# LEF file generated by Abstract Generator version 5.5.10 on Jul 31 16:51:52 2004
#
# Contains LEF for all bins.
# Options:   [x] Antenna
#            [x] Geometry
#            [x] Technology

VERSION 5.4 ;
NAMESCASESENSITIVE ON ;
BUSBITCHARS "[]" ;
DIVIDERCHAR "/" ;
UNITS
  DATABASE MICRONS 1000 ;
END UNITS

USEMINSPACING OBS ON ;
USEMINSPACING PIN OFF ;
CLEARANCEMEASURE EUCLIDEAN ;


MANUFACTURINGGRID 0.15 ;

LAYER nwell
  TYPE	MASTERSLICE ;
END nwell

LAYER nactive
  TYPE	MASTERSLICE ;
END nactive

LAYER pactive
  TYPE	MASTERSLICE ;
END pactive

LAYER poly
  TYPE	MASTERSLICE ;
END poly

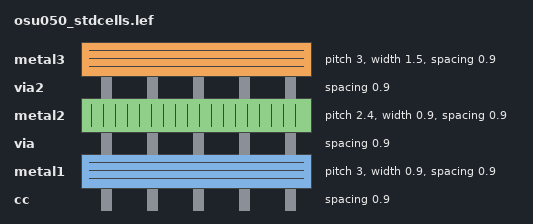
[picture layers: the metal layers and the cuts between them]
LAYER cc
  TYPE	CUT ;
  SPACING	0.9 ;
END cc

LAYER metal1
  TYPE		ROUTING ;
  DIRECTION	HORIZONTAL ;
  PITCH		3  ;
  OFFSET	1.5 ;
  WIDTH		0.9 ;
  SPACING	0.9 ;
  RESISTANCE	RPERSQ 0.09 ;
  CAPACITANCE	CPERSQDIST 3.2e-05 ;
END metal1

LAYER via
  TYPE	CUT ;
  SPACING	0.9 ;
END via

LAYER metal2
  TYPE		ROUTING ;
  DIRECTION	VERTICAL ;
  PITCH		2.4  ;
  OFFSET	1.2 ;
  WIDTH		0.9 ;
  SPACING	0.9 ;
  RESISTANCE	RPERSQ 0.09 ;
  CAPACITANCE	CPERSQDIST 1.6e-05 ;
END metal2

LAYER via2
  TYPE	CUT ;
  SPACING	0.9 ;
END via2

LAYER metal3
  TYPE		ROUTING ;
  DIRECTION	HORIZONTAL ;
  PITCH		3  ;
  OFFSET	1.5 ;
  WIDTH		1.5 ;
  SPACING	0.9 ;
  RESISTANCE	RPERSQ 0.05 ;
  CAPACITANCE	CPERSQDIST 1e-05 ;
END metal3

SPACING
  SAMENET cc  via	0.150 ;
  SAMENET via  via2	0.150 ;
END SPACING

VIA M2_M1 DEFAULT
  LAYER metal1 ;
    RECT -0.600 -0.600 0.600 0.600 ;
  LAYER via ;
    RECT -0.300 -0.300 0.300 0.300 ;
  LAYER metal2 ;
    RECT -0.600 -0.600 0.600 0.600 ;
END M2_M1

VIA M3_M2 DEFAULT
  LAYER metal2 ;
    RECT -0.600 -0.600 0.600 0.600 ;
  LAYER via2 ;
    RECT -0.300 -0.300 0.300 0.300 ;
  LAYER metal3 ;
    RECT -0.900 -0.900 0.900 0.900 ;
END M3_M2


VIARULE viagen21 GENERATE
  LAYER metal1 ;
    DIRECTION HORIZONTAL ;
    WIDTH 1.2 TO 120 ;
    OVERHANG 0.3 ;
    METALOVERHANG 0 ;
  LAYER metal2 ;
    DIRECTION VERTICAL ;
    WIDTH 1.2 TO 120 ;
    OVERHANG 0.3 ;
    METALOVERHANG 0 ;
  LAYER via ;
    RECT -0.3 -0.3 0.3 0.3 ;
    SPACING 1.5 BY 1.5 ;
END viagen21

VIARULE viagen32 GENERATE
  LAYER metal3 ;
    DIRECTION HORIZONTAL ;
    WIDTH 1.8 TO 180 ;
    OVERHANG 0.6 ;
    METALOVERHANG 0 ;
  LAYER metal2 ;
    DIRECTION VERTICAL ;
    WIDTH 1.2 TO 120 ;
    OVERHANG 0.6 ;
    METALOVERHANG 0 ;
  LAYER via2 ;
    RECT -0.3 -0.3 0.3 0.3 ;
    SPACING 2.1 BY 2.1 ;
END viagen32

VIARULE TURN1 GENERATE
  LAYER metal1 ;
    DIRECTION HORIZONTAL ;
  LAYER metal1 ;
    DIRECTION VERTICAL ;
END TURN1

VIARULE TURN2 GENERATE
  LAYER metal2 ;
    DIRECTION HORIZONTAL ;
  LAYER metal2 ;
    DIRECTION VERTICAL ;
END TURN2

VIARULE TURN3 GENERATE
  LAYER metal3 ;
    DIRECTION HORIZONTAL ;
  LAYER metal3 ;
    DIRECTION VERTICAL ;
END TURN3

SITE  corner
    CLASS	PAD ;
    SYMMETRY	R90 Y ;
    SIZE	300.000 BY 300.000 ;
END  corner

SITE  IO
    CLASS	PAD ;
    SYMMETRY	Y ;
    SIZE	90.000 BY 300.000 ;
END  IO

SITE  core
    CLASS	CORE ;
    SYMMETRY	Y ;
    SIZE	2.400 BY 30.000 ;
END  core

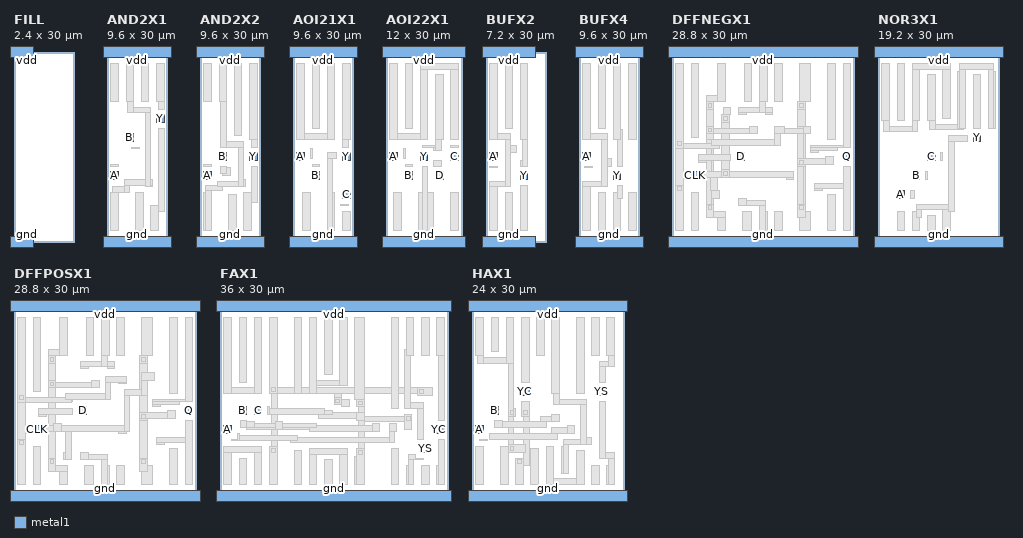
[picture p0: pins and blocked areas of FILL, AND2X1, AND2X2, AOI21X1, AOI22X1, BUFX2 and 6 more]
MACRO FILL
  CLASS  CORE ;
  FOREIGN FILL 0.000 0.000 ;
  ORIGIN 0.000 0.000 ;
  SIZE 2.400 BY 30.000 ;
  SYMMETRY X Y  ;
  SITE core ;
  PIN gnd
    DIRECTION INOUT ;
    USE GROUND ;
    SHAPE ABUTMENT ;
    PORT
      LAYER metal1 ;
        RECT -0.600 -0.900 3.000 0.900 ;
    END
  END gnd
  PIN vdd
    DIRECTION INOUT ;
    USE POWER ;
    SHAPE ABUTMENT ;
    PORT
      LAYER metal1 ;
        RECT -0.600 29.100 3.000 30.900 ;
    END
  END vdd
END FILL

MACRO AND2X1
  CLASS  CORE ;
  FOREIGN AND2X1 0.000 0.000 ;
  ORIGIN 0.000 0.000 ;
  SIZE 9.600 BY 30.000 ;
  SYMMETRY X Y  ;
  SITE core ;
  PIN A
    DIRECTION INPUT ;
    PORT
      LAYER metal1 ;
        RECT 0.600 9.900 1.800 11.100 ;
    END
  END A
  PIN B
    DIRECTION INPUT ;
    PORT
      LAYER metal1 ;
        RECT 3.000 15.900 4.200 17.100 ;
    END
  END B
  PIN gnd
    DIRECTION INOUT ;
    USE GROUND ;
    SHAPE ABUTMENT ;
    PORT
      LAYER metal1 ;
        RECT -0.600 -0.900 10.200 0.900 ;
    END
  END gnd
  PIN Y
    DIRECTION OUTPUT ;
    PORT
      LAYER metal1 ;
        RECT 7.800 18.900 9.000 20.100 ;
    END
  END Y
  PIN vdd
    DIRECTION INOUT ;
    USE POWER ;
    SHAPE ABUTMENT ;
    PORT
      LAYER metal1 ;
        RECT -0.600 29.100 10.200 30.900 ;
    END
  END vdd
  OBS 
      LAYER metal1 ;
        RECT 0.600 22.200 1.800 28.200 ;
        RECT 0.600 12.000 1.800 12.300 ;
        RECT 3.900 14.700 5.100 15.000 ;
        RECT 4.500 1.800 5.700 7.800 ;
        RECT 5.400 22.200 6.600 28.200 ;
        RECT 0.600 1.800 1.800 7.800 ;
        RECT 0.900 7.800 3.600 8.700 ;
        RECT 2.700 7.800 3.600 9.900 ;
        RECT 6.000 8.700 7.200 9.900 ;
        RECT 2.700 9.000 7.200 9.900 ;
        RECT 6.000 8.700 6.900 21.300 ;
        RECT 3.300 20.400 6.900 21.300 ;
        RECT 3.300 20.400 4.200 28.200 ;
        RECT 3.000 22.200 4.200 28.200 ;
        RECT 8.100 21.000 9.000 28.200 ;
        RECT 7.800 22.200 9.000 28.200 ;
        RECT 6.900 1.800 8.100 5.700 ;
        RECT 8.100 4.800 9.000 18.000 ;
  END 
END AND2X1

MACRO AND2X2
  CLASS  CORE ;
  FOREIGN AND2X2 0.000 0.000 ;
  ORIGIN 0.000 0.000 ;
  SIZE 9.600 BY 30.000 ;
  SYMMETRY X Y  ;
  SITE core ;
  PIN A
    DIRECTION INPUT ;
    PORT
      LAYER metal1 ;
        RECT 0.600 9.900 1.800 11.100 ;
    END
  END A
  PIN B
    DIRECTION INPUT ;
    PORT
      LAYER metal1 ;
        RECT 3.000 12.900 4.200 14.100 ;
    END
  END B
  PIN gnd
    DIRECTION INOUT ;
    USE GROUND ;
    SHAPE ABUTMENT ;
    PORT
      LAYER metal1 ;
        RECT -0.600 -0.900 10.200 0.900 ;
    END
  END gnd
  PIN Y
    DIRECTION OUTPUT ;
    PORT
      LAYER metal1 ;
        RECT 7.800 12.900 9.000 14.100 ;
    END
  END Y
  PIN vdd
    DIRECTION INOUT ;
    USE POWER ;
    SHAPE ABUTMENT ;
    PORT
      LAYER metal1 ;
        RECT -0.600 29.100 10.200 30.900 ;
    END
  END vdd
  OBS 
      LAYER metal1 ;
        RECT 0.600 22.200 1.800 28.200 ;
        RECT 0.600 12.000 1.800 12.300 ;
        RECT 3.600 10.500 4.800 11.700 ;
        RECT 3.300 10.800 4.200 12.000 ;
        RECT 4.500 1.800 5.700 7.500 ;
        RECT 5.400 16.800 6.600 28.200 ;
        RECT 0.600 1.800 1.800 7.800 ;
        RECT 0.900 1.800 1.800 9.000 ;
        RECT 0.900 8.100 3.600 9.000 ;
        RECT 2.700 8.700 7.200 9.600 ;
        RECT 6.000 8.700 7.200 9.900 ;
        RECT 6.000 8.700 6.900 15.900 ;
        RECT 3.300 15.000 6.900 15.900 ;
        RECT 3.300 15.000 4.200 28.200 ;
        RECT 3.000 22.200 4.200 28.200 ;
        RECT 8.100 15.000 9.000 28.200 ;
        RECT 7.800 16.200 9.000 28.200 ;
        RECT 6.900 1.800 8.100 7.800 ;
        RECT 8.100 6.300 9.000 12.000 ;
  END 
END AND2X2

MACRO AOI21X1
  CLASS  CORE ;
  FOREIGN AOI21X1 0.000 0.000 ;
  ORIGIN 0.000 0.000 ;
  SIZE 9.600 BY 30.000 ;
  SYMMETRY X Y  ;
  SITE core ;
  PIN A
    DIRECTION INPUT ;
    PORT
      LAYER metal1 ;
        RECT 0.600 12.900 1.800 14.100 ;
    END
  END A
  PIN B
    DIRECTION INPUT ;
    PORT
      LAYER metal1 ;
        RECT 3.000 9.900 4.200 11.100 ;
    END
  END B
  PIN C
    DIRECTION INPUT ;
    PORT
      LAYER metal1 ;
        RECT 7.800 6.900 9.000 8.100 ;
    END
  END C
  PIN gnd
    DIRECTION INOUT ;
    USE GROUND ;
    SHAPE ABUTMENT ;
    PORT
      LAYER metal1 ;
        RECT -0.600 -0.900 10.200 0.900 ;
    END
  END gnd
  PIN Y
    DIRECTION OUTPUT ;
    PORT
      LAYER metal1 ;
        RECT 7.800 12.900 9.000 14.100 ;
    END
  END Y
  PIN vdd
    DIRECTION INOUT ;
    USE POWER ;
    SHAPE ABUTMENT ;
    PORT
      LAYER metal1 ;
        RECT -0.600 29.100 10.200 30.900 ;
    END
  END vdd
  OBS 
      LAYER metal1 ;
        RECT 1.500 1.800 2.700 7.800 ;
        RECT 2.700 13.200 3.000 14.700 ;
        RECT 3.000 18.000 4.200 28.200 ;
        RECT 3.000 12.000 4.200 12.300 ;
        RECT 0.600 16.200 6.600 17.100 ;
        RECT 0.600 16.200 1.800 28.200 ;
        RECT 5.400 16.200 6.600 28.200 ;
        RECT 5.400 1.800 6.600 7.800 ;
        RECT 5.400 1.800 6.300 14.100 ;
        RECT 5.400 13.200 6.900 14.100 ;
        RECT 7.500 5.700 8.700 6.000 ;
        RECT 7.800 15.000 8.700 28.200 ;
        RECT 7.800 16.200 9.000 28.200 ;
        RECT 7.800 1.800 9.000 4.800 ;
  END 
END AOI21X1

MACRO AOI22X1
  CLASS  CORE ;
  FOREIGN AOI22X1 0.000 0.000 ;
  ORIGIN 0.000 0.000 ;
  SIZE 12.000 BY 30.000 ;
  SYMMETRY X Y  ;
  SITE core ;
  PIN A
    DIRECTION INPUT ;
    PORT
      LAYER metal1 ;
        RECT 0.600 12.900 1.800 14.100 ;
    END
  END A
  PIN B
    DIRECTION INPUT ;
    PORT
      LAYER metal1 ;
        RECT 3.000 9.900 4.200 11.100 ;
    END
  END B
  PIN C
    DIRECTION INPUT ;
    PORT
      LAYER metal1 ;
        RECT 10.200 12.900 11.400 14.100 ;
    END
  END C
  PIN D
    DIRECTION INPUT ;
    PORT
      LAYER metal1 ;
        RECT 7.800 9.900 9.000 11.100 ;
    END
  END D
  PIN gnd
    DIRECTION INOUT ;
    USE GROUND ;
    SHAPE ABUTMENT ;
    PORT
      LAYER metal1 ;
        RECT -0.600 -0.900 12.600 0.900 ;
    END
  END gnd
  PIN Y
    DIRECTION OUTPUT ;
    PORT
      LAYER metal1 ;
        RECT 5.400 12.900 6.600 14.100 ;
    END
  END Y
  PIN vdd
    DIRECTION INOUT ;
    USE POWER ;
    SHAPE ABUTMENT ;
    PORT
      LAYER metal1 ;
        RECT -0.600 29.100 12.600 30.900 ;
    END
  END vdd
  OBS 
      LAYER metal1 ;
        RECT 1.200 1.800 2.400 7.800 ;
        RECT 2.700 13.200 3.000 14.700 ;
        RECT 3.000 18.000 4.200 28.200 ;
        RECT 3.000 12.000 4.200 12.300 ;
        RECT 5.100 1.800 7.500 7.800 ;
        RECT 5.700 1.800 6.600 12.000 ;
        RECT 7.500 12.000 8.700 12.900 ;
        RECT 7.500 14.400 8.700 15.300 ;
        RECT 5.700 15.000 8.700 15.300 ;
        RECT 7.800 14.400 8.700 26.400 ;
        RECT 7.800 16.200 9.000 26.400 ;
        RECT 0.600 16.200 6.600 17.100 ;
        RECT 5.400 16.200 6.600 28.200 ;
        RECT 0.600 16.200 1.800 28.200 ;
        RECT 10.200 16.200 11.400 28.200 ;
        RECT 5.400 27.300 11.400 28.200 ;
        RECT 10.200 15.000 11.400 15.300 ;
        RECT 10.200 1.800 11.400 7.800 ;
  END 
END AOI22X1

MACRO BUFX2
  CLASS  CORE ;
  FOREIGN BUFX2 0.000 0.000 ;
  ORIGIN 0.000 0.000 ;
  SIZE 7.200 BY 30.000 ;
  SYMMETRY X Y  ;
  SITE core ;
  PIN A
    DIRECTION INPUT ;
    PORT
      LAYER metal1 ;
        RECT 0.600 12.900 1.800 14.100 ;
    END
  END A
  PIN gnd
    DIRECTION INOUT ;
    USE GROUND ;
    SHAPE ABUTMENT ;
    PORT
      LAYER metal1 ;
        RECT -0.600 -0.900 7.800 0.900 ;
    END
  END gnd
  PIN Y
    DIRECTION OUTPUT ;
    PORT
      LAYER metal1 ;
        RECT 5.400 9.900 6.600 11.100 ;
    END
  END Y
  PIN vdd
    DIRECTION INOUT ;
    USE POWER ;
    SHAPE ABUTMENT ;
    PORT
      LAYER metal1 ;
        RECT -0.600 29.100 7.800 30.900 ;
    END
  END vdd
  OBS 
      LAYER metal1 ;
        RECT 0.600 11.700 1.800 12.000 ;
        RECT 3.000 18.000 4.200 28.200 ;
        RECT 3.000 1.800 4.200 7.800 ;
        RECT 0.600 1.800 1.800 9.600 ;
        RECT 0.600 8.700 3.900 9.600 ;
        RECT 3.000 14.100 4.800 15.300 ;
        RECT 3.000 8.700 3.900 17.100 ;
        RECT 0.600 16.200 3.900 17.100 ;
        RECT 0.600 16.200 1.800 28.200 ;
        RECT 5.400 12.000 6.600 12.900 ;
        RECT 5.700 12.000 6.600 28.200 ;
        RECT 5.400 16.200 6.600 28.200 ;
        RECT 5.400 1.800 6.600 9.000 ;
  END 
END BUFX2

MACRO BUFX4
  CLASS  CORE ;
  FOREIGN BUFX4 0.000 0.000 ;
  ORIGIN 0.000 0.000 ;
  SIZE 9.600 BY 30.000 ;
  SYMMETRY X Y  ;
  SITE core ;
  PIN A
    DIRECTION INPUT ;
    PORT
      LAYER metal1 ;
        RECT 0.600 12.900 1.800 14.100 ;
    END
  END A
  PIN gnd
    DIRECTION INOUT ;
    USE GROUND ;
    SHAPE ABUTMENT ;
    PORT
      LAYER metal1 ;
        RECT -0.600 -0.900 10.200 0.900 ;
    END
  END gnd
  PIN Y
    DIRECTION OUTPUT ;
    PORT
      LAYER metal1 ;
        RECT 5.400 9.900 6.600 11.100 ;
    END
  END Y
  PIN vdd
    DIRECTION INOUT ;
    USE POWER ;
    SHAPE ABUTMENT ;
    PORT
      LAYER metal1 ;
        RECT -0.600 29.100 10.200 30.900 ;
    END
  END vdd
  OBS 
      LAYER metal1 ;
        RECT 0.900 11.700 2.100 12.000 ;
        RECT 3.000 18.000 4.200 28.200 ;
        RECT 3.000 1.800 4.200 7.800 ;
        RECT 0.600 1.800 1.800 9.600 ;
        RECT 0.600 8.700 4.500 9.600 ;
        RECT 3.600 12.000 5.100 13.200 ;
        RECT 3.600 8.700 4.500 17.100 ;
        RECT 0.600 16.200 4.500 17.100 ;
        RECT 0.600 16.200 1.800 28.200 ;
        RECT 6.000 12.000 6.900 17.700 ;
        RECT 5.400 16.200 6.600 28.200 ;
        RECT 5.400 1.800 6.600 7.800 ;
        RECT 6.000 6.900 6.900 9.000 ;
        RECT 7.800 16.200 9.000 28.200 ;
        RECT 7.800 1.800 9.000 7.800 ;
  END 
END BUFX4

MACRO DFFNEGX1
  CLASS  CORE ;
  FOREIGN DFFNEGX1 0.000 0.000 ;
  ORIGIN 0.000 0.000 ;
  SIZE 28.800 BY 30.000 ;
  SYMMETRY X Y  ;
  SITE core ;
  PIN Q
    DIRECTION OUTPUT ;
    PORT
      LAYER metal1 ;
        RECT 27.000 12.900 28.200 14.100 ;
    END
  END Q
  PIN CLK
    DIRECTION INPUT ;
    PORT
      LAYER metal1 ;
        RECT 3.000 9.900 4.200 11.100 ;
    END
  END CLK
  PIN D
    DIRECTION INPUT ;
    PORT
      LAYER metal1 ;
        RECT 10.200 12.900 11.400 14.100 ;
    END
  END D
  PIN gnd
    DIRECTION INOUT ;
    USE GROUND ;
    SHAPE ABUTMENT ;
    PORT
      LAYER metal1 ;
        RECT -0.600 -0.900 29.400 0.900 ;
    END
  END gnd
  PIN vdd
    DIRECTION INOUT ;
    USE POWER ;
    SHAPE ABUTMENT ;
    PORT
      LAYER metal1 ;
        RECT -0.600 29.100 29.400 30.900 ;
    END
  END vdd
  OBS 
      LAYER metal2 ;
        RECT 0.600 7.800 1.800 16.200 ;
        RECT 5.400 4.800 6.600 15.000 ;
        RECT 5.400 4.800 6.300 22.200 ;
        RECT 5.400 16.200 6.600 22.200 ;
        RECT 7.800 10.200 9.000 20.100 ;
        RECT 19.800 4.800 21.000 17.100 ;
        RECT 19.800 4.800 20.700 22.200 ;
        RECT 19.800 18.300 21.000 22.200 ;
      LAYER metal1 ;
        RECT 0.600 1.800 1.800 9.000 ;
        RECT 1.800 9.900 2.100 11.100 ;
        RECT 3.000 16.500 4.200 28.200 ;
        RECT 3.000 1.800 4.200 7.800 ;
        RECT 5.400 21.000 6.600 23.100 ;
        RECT 5.400 22.200 8.400 23.100 ;
        RECT 7.200 22.200 8.400 28.200 ;
        RECT 7.200 1.800 8.400 4.800 ;
        RECT 5.400 3.900 8.400 4.800 ;
        RECT 5.400 3.900 6.600 6.000 ;
        RECT 7.800 18.900 9.000 20.100 ;
        RECT 8.100 20.100 9.300 21.300 ;
        RECT 4.200 12.600 5.400 13.800 ;
        RECT 4.200 12.900 9.300 13.800 ;
        RECT 11.400 22.200 12.600 28.200 ;
        RECT 11.100 1.800 12.600 4.800 ;
        RECT 5.400 17.100 13.500 18.000 ;
        RECT 5.400 17.100 6.600 18.300 ;
        RECT 12.300 17.100 13.500 18.300 ;
        RECT 13.800 1.800 15.000 4.800 ;
        RECT 13.800 1.800 14.700 6.600 ;
        RECT 10.500 5.700 14.700 6.600 ;
        RECT 10.500 5.700 11.700 6.900 ;
        RECT 10.500 20.100 11.700 21.300 ;
        RECT 14.700 20.100 15.900 21.300 ;
        RECT 10.500 20.400 15.900 21.300 ;
        RECT 13.800 20.400 14.700 28.200 ;
        RECT 13.800 22.200 15.000 28.200 ;
        RECT 16.200 22.200 17.400 28.200 ;
        RECT 16.200 1.800 17.400 4.800 ;
        RECT 6.300 6.900 7.500 8.100 ;
        RECT 6.000 8.100 7.200 11.100 ;
        RECT 18.000 9.900 19.200 11.100 ;
        RECT 5.100 10.200 19.200 11.100 ;
        RECT 7.800 10.200 9.000 11.400 ;
        RECT 19.800 21.000 21.000 22.200 ;
        RECT 20.100 22.200 21.900 28.200 ;
        RECT 0.600 14.700 7.500 15.600 ;
        RECT 6.300 15.300 17.100 16.200 ;
        RECT 16.200 15.300 17.100 18.300 ;
        RECT 16.200 17.100 21.900 18.000 ;
        RECT 16.200 17.100 17.700 18.300 ;
        RECT 20.700 17.100 21.900 18.300 ;
        RECT 0.600 14.700 1.800 28.200 ;
        RECT 20.100 1.800 21.900 4.800 ;
        RECT 19.800 3.900 21.000 6.000 ;
        RECT 19.800 12.000 21.000 13.200 ;
        RECT 19.800 12.300 25.500 13.200 ;
        RECT 24.300 12.300 25.500 13.500 ;
        RECT 24.600 16.200 25.800 28.200 ;
        RECT 24.600 1.800 25.800 7.500 ;
        RECT 21.900 14.100 23.100 15.300 ;
        RECT 21.900 14.400 26.100 15.300 ;
        RECT 21.900 15.000 28.200 15.300 ;
        RECT 27.000 15.000 28.200 28.200 ;
        RECT 22.500 8.100 23.700 9.300 ;
        RECT 22.500 8.400 28.200 9.300 ;
        RECT 27.000 1.800 28.200 12.000 ;
      LAYER via ;
        RECT 0.900 15.300 1.500 15.900 ;
        RECT 0.900 8.100 1.500 8.700 ;
        RECT 5.700 21.300 6.300 21.900 ;
        RECT 5.700 17.400 6.300 18.000 ;
        RECT 5.700 5.100 6.300 5.700 ;
        RECT 8.100 19.200 8.700 19.800 ;
        RECT 8.100 10.500 8.700 11.100 ;
        RECT 20.100 21.300 20.700 21.900 ;
        RECT 20.100 12.300 20.700 12.900 ;
        RECT 20.100 5.100 20.700 5.700 ;
  END 
END DFFNEGX1

MACRO NOR3X1
  CLASS  CORE ;
  FOREIGN NOR3X1 0.000 0.000 ;
  ORIGIN 0.000 0.000 ;
  SIZE 19.200 BY 30.000 ;
  SYMMETRY X Y  ;
  SITE core ;
  PIN A
    DIRECTION INPUT ;
    PORT
      LAYER metal1 ;
        RECT 3.000 6.900 4.200 8.100 ;
    END
  END A
  PIN B
    DIRECTION INPUT ;
    PORT
      LAYER metal1 ;
        RECT 5.400 9.900 6.600 11.100 ;
    END
  END B
  PIN C
    DIRECTION INPUT ;
    PORT
      LAYER metal1 ;
        RECT 7.800 12.900 9.000 14.100 ;
    END
  END C
  PIN gnd
    DIRECTION INOUT ;
    USE GROUND ;
    SHAPE ABUTMENT ;
    PORT
      LAYER metal1 ;
        RECT -0.600 -0.900 19.800 0.900 ;
    END
  END gnd
  PIN Y
    DIRECTION OUTPUT ;
    PORT
      LAYER metal1 ;
        RECT 15.000 15.900 16.200 17.100 ;
    END
  END Y
  PIN vdd
    DIRECTION INOUT ;
    USE POWER ;
    SHAPE ABUTMENT ;
    PORT
      LAYER metal1 ;
        RECT -0.600 29.100 19.800 30.900 ;
    END
  END vdd
  OBS 
      LAYER metal1 ;
        RECT 3.000 19.200 4.200 28.200 ;
        RECT 3.000 1.800 4.200 4.800 ;
        RECT 5.100 6.900 5.700 8.100 ;
        RECT 7.500 9.900 7.800 11.100 ;
        RECT 7.800 1.800 9.000 4.200 ;
        RECT 9.900 12.900 10.200 14.100 ;
        RECT 0.900 17.400 6.300 18.300 ;
        RECT 5.400 17.400 6.300 28.200 ;
        RECT 5.400 19.200 6.600 28.200 ;
        RECT 0.900 17.400 1.800 28.200 ;
        RECT 0.600 19.200 1.800 28.200 ;
        RECT 10.200 19.500 11.400 28.200 ;
        RECT 5.400 27.300 11.400 28.200 ;
        RECT 5.400 1.800 6.600 4.800 ;
        RECT 6.000 3.900 6.900 6.000 ;
        RECT 10.200 1.800 11.400 6.000 ;
        RECT 6.000 5.100 12.000 6.000 ;
        RECT 11.100 4.800 12.000 16.800 ;
        RECT 11.100 15.900 14.100 16.800 ;
        RECT 15.000 18.000 16.200 26.400 ;
        RECT 8.100 17.700 13.500 18.600 ;
        RECT 8.100 17.700 9.000 26.400 ;
        RECT 7.800 19.200 9.000 26.400 ;
        RECT 12.600 18.000 13.800 27.000 ;
        RECT 17.400 18.000 18.600 27.000 ;
        RECT 12.900 18.000 13.800 28.200 ;
        RECT 17.400 18.000 18.300 28.200 ;
        RECT 12.900 27.300 18.300 28.200 ;
  END 
END NOR3X1

MACRO DFFPOSX1
  CLASS  CORE ;
  FOREIGN DFFPOSX1 0.000 0.000 ;
  ORIGIN 0.000 0.000 ;
  SIZE 28.800 BY 30.000 ;
  SYMMETRY X Y  ;
  SITE core ;
  PIN Q
    DIRECTION OUTPUT ;
    PORT
      LAYER metal1 ;
        RECT 27.000 12.900 28.200 14.100 ;
    END
  END Q
  PIN CLK
    DIRECTION INPUT ;
    PORT
      LAYER metal1 ;
        RECT 3.000 9.900 4.200 11.100 ;
    END
  END CLK
  PIN D
    DIRECTION INPUT ;
    PORT
      LAYER metal1 ;
        RECT 10.200 12.900 11.400 14.100 ;
    END
  END D
  PIN gnd
    DIRECTION INOUT ;
    USE GROUND ;
    SHAPE ABUTMENT ;
    PORT
      LAYER metal1 ;
        RECT -0.600 -0.900 29.400 0.900 ;
    END
  END gnd
  PIN vdd
    DIRECTION INOUT ;
    USE POWER ;
    SHAPE ABUTMENT ;
    PORT
      LAYER metal1 ;
        RECT -0.600 29.100 29.400 30.900 ;
    END
  END vdd
  OBS 
      LAYER metal2 ;
        RECT 0.600 7.800 1.800 16.200 ;
        RECT 5.400 4.800 6.600 22.200 ;
        RECT 19.800 4.800 21.000 22.200 ;
      LAYER metal1 ;
        RECT 0.600 1.800 1.800 9.000 ;
        RECT 1.800 9.900 2.100 11.100 ;
        RECT 3.000 16.500 4.200 28.200 ;
        RECT 3.000 1.800 4.200 7.800 ;
        RECT 5.400 21.000 6.600 23.100 ;
        RECT 5.400 22.200 8.400 23.100 ;
        RECT 7.200 22.200 8.400 28.200 ;
        RECT 7.200 1.800 8.400 4.800 ;
        RECT 5.400 3.900 8.400 4.800 ;
        RECT 5.400 3.900 6.600 6.000 ;
        RECT 3.900 12.600 5.100 13.800 ;
        RECT 3.900 12.900 9.300 13.800 ;
        RECT 11.400 22.200 12.600 28.200 ;
        RECT 11.100 1.800 12.600 4.800 ;
        RECT 5.400 17.100 13.500 18.000 ;
        RECT 5.400 17.100 6.600 18.300 ;
        RECT 12.300 17.100 13.500 18.300 ;
        RECT 13.800 1.800 15.000 4.800 ;
        RECT 13.800 1.800 14.700 6.600 ;
        RECT 10.500 5.700 14.700 6.600 ;
        RECT 10.500 5.700 11.700 6.900 ;
        RECT 10.500 20.100 11.700 21.300 ;
        RECT 14.700 20.100 15.900 21.300 ;
        RECT 10.500 20.400 15.900 21.300 ;
        RECT 13.800 20.400 14.700 28.200 ;
        RECT 13.800 22.200 15.000 28.200 ;
        RECT 16.200 22.200 17.400 28.200 ;
        RECT 16.200 1.800 17.400 4.800 ;
        RECT 0.600 15.000 9.300 15.600 ;
        RECT 0.600 14.700 9.000 15.600 ;
        RECT 8.100 15.300 15.300 16.200 ;
        RECT 14.400 15.300 15.300 18.900 ;
        RECT 16.500 17.700 17.700 18.900 ;
        RECT 14.400 18.000 17.700 18.900 ;
        RECT 0.600 14.700 1.800 28.200 ;
        RECT 19.800 21.000 21.000 22.200 ;
        RECT 20.100 22.200 21.900 28.200 ;
        RECT 20.100 1.800 21.900 4.800 ;
        RECT 19.800 3.900 21.000 6.000 ;
        RECT 7.800 5.700 9.000 6.900 ;
        RECT 8.100 5.700 9.000 11.100 ;
        RECT 16.500 9.900 17.700 11.100 ;
        RECT 5.100 10.200 18.300 11.100 ;
        RECT 6.300 10.200 7.500 11.400 ;
        RECT 17.400 10.200 18.300 16.800 ;
        RECT 17.400 15.900 21.000 16.800 ;
        RECT 20.100 15.900 21.000 19.500 ;
        RECT 20.100 18.300 22.200 19.500 ;
        RECT 19.800 12.000 21.000 13.200 ;
        RECT 19.800 12.300 25.500 13.200 ;
        RECT 24.300 12.300 25.500 13.500 ;
        RECT 24.600 16.200 25.800 28.200 ;
        RECT 24.600 1.800 25.800 7.500 ;
        RECT 21.900 14.100 23.100 15.300 ;
        RECT 21.900 14.400 26.100 15.300 ;
        RECT 21.900 15.000 28.200 15.300 ;
        RECT 27.000 15.000 28.200 28.200 ;
        RECT 22.500 8.100 23.700 9.300 ;
        RECT 22.500 8.400 28.200 9.300 ;
        RECT 27.000 1.800 28.200 12.000 ;
      LAYER via ;
        RECT 0.900 15.300 1.500 15.900 ;
        RECT 0.900 8.100 1.500 8.700 ;
        RECT 5.700 21.300 6.300 21.900 ;
        RECT 5.700 17.400 6.300 18.000 ;
        RECT 5.700 5.100 6.300 5.700 ;
        RECT 20.100 21.300 20.700 21.900 ;
        RECT 20.100 12.300 20.700 12.900 ;
        RECT 20.100 5.100 20.700 5.700 ;
  END 
END DFFPOSX1

MACRO FAX1
  CLASS  CORE ;
  FOREIGN FAX1 0.000 0.000 ;
  ORIGIN 0.000 0.000 ;
  SIZE 36.000 BY 30.000 ;
  SYMMETRY X Y  ;
  SITE core ;
  PIN YC
    DIRECTION OUTPUT ;
    PORT
      LAYER metal1 ;
        RECT 34.200 9.900 35.400 11.100 ;
    END
  END YC
  PIN YS
    DIRECTION OUTPUT ;
    PORT
      LAYER metal1 ;
        RECT 31.800 6.900 33.000 8.100 ;
    END
  END YS
  PIN A
    DIRECTION INPUT ;
    PORT
      LAYER metal1 ;
        RECT 0.600 9.900 1.800 11.100 ;
    END
  END A
  PIN B
    DIRECTION INPUT ;
    PORT
      LAYER metal1 ;
        RECT 3.000 12.900 4.200 14.100 ;
    END
  END B
  PIN C
    DIRECTION INPUT ;
    PORT
      LAYER metal1 ;
        RECT 5.400 12.900 6.600 14.100 ;
    END
  END C
  PIN gnd
    DIRECTION INOUT ;
    USE GROUND ;
    SHAPE ABUTMENT ;
    PORT
      LAYER metal1 ;
        RECT -0.600 -0.900 36.600 0.900 ;
    END
  END gnd
  PIN vdd
    DIRECTION INOUT ;
    USE POWER ;
    SHAPE ABUTMENT ;
    PORT
      LAYER metal1 ;
        RECT -0.600 29.100 36.600 30.900 ;
    END
  END vdd
  OBS 
      LAYER metal2 ;
        RECT 21.600 6.300 22.800 7.500 ;
        RECT 21.900 11.700 30.300 12.600 ;
        RECT 29.100 11.700 30.300 12.900 ;
        RECT 21.900 6.300 22.800 15.300 ;
        RECT 21.600 14.100 22.800 15.300 ;
        RECT 7.800 6.600 9.000 7.800 ;
        RECT 18.000 14.400 19.200 17.100 ;
        RECT 31.200 15.900 32.400 17.100 ;
        RECT 7.800 16.200 32.400 17.100 ;
        RECT 8.100 6.600 9.000 17.400 ;
        RECT 7.800 16.200 9.000 17.400 ;
      LAYER metal1 ;
        RECT 3.000 18.000 4.200 28.200 ;
        RECT 3.000 1.800 4.200 6.000 ;
        RECT 0.600 16.200 6.600 17.100 ;
        RECT 0.600 16.200 1.800 28.200 ;
        RECT 5.400 16.200 6.600 28.200 ;
        RECT 0.600 1.800 1.800 7.800 ;
        RECT 5.400 1.800 6.600 7.800 ;
        RECT 0.600 6.900 6.600 7.800 ;
        RECT 7.800 16.200 9.000 28.200 ;
        RECT 7.800 1.800 9.000 7.800 ;
        RECT 11.700 16.200 12.900 28.200 ;
        RECT 11.700 1.800 12.900 7.200 ;
        RECT 16.500 19.200 17.700 28.200 ;
        RECT 16.500 1.800 17.700 5.700 ;
        RECT 14.100 17.400 20.100 18.300 ;
        RECT 14.100 16.200 15.300 28.200 ;
        RECT 18.900 17.400 20.100 28.200 ;
        RECT 14.100 1.800 15.300 7.500 ;
        RECT 18.900 1.800 20.100 7.500 ;
        RECT 14.100 6.600 20.100 7.500 ;
        RECT 19.200 14.100 20.400 15.300 ;
        RECT 18.000 14.400 19.200 15.600 ;
        RECT 21.600 14.100 22.800 28.200 ;
        RECT 21.300 15.300 22.800 28.200 ;
        RECT 15.600 12.300 22.800 13.200 ;
        RECT 21.600 12.000 22.800 13.200 ;
        RECT 7.500 12.900 17.700 13.500 ;
        RECT 7.500 12.900 16.500 13.800 ;
        RECT 7.500 12.900 7.800 14.100 ;
        RECT 21.300 1.800 22.800 6.300 ;
        RECT 21.600 1.800 22.800 7.500 ;
        RECT 4.200 10.500 25.200 11.100 ;
        RECT 14.100 10.200 25.200 11.100 ;
        RECT 3.300 10.800 15.300 11.400 ;
        RECT 24.000 10.200 25.200 11.400 ;
        RECT 3.300 10.800 5.400 11.700 ;
        RECT 8.700 10.500 9.900 11.700 ;
        RECT 3.300 10.800 4.200 12.000 ;
        RECT 1.800 8.700 27.600 9.000 ;
        RECT 11.100 8.400 27.600 9.300 ;
        RECT 2.700 8.700 12.300 9.600 ;
        RECT 2.700 8.700 3.000 9.900 ;
        RECT 26.700 8.400 27.600 11.400 ;
        RECT 26.700 10.200 27.900 11.400 ;
        RECT 27.000 13.800 28.200 28.200 ;
        RECT 27.000 1.800 28.200 7.500 ;
        RECT 29.100 10.500 30.300 12.900 ;
        RECT 31.200 9.000 32.100 14.700 ;
        RECT 29.100 13.800 32.100 14.700 ;
        RECT 29.100 13.800 30.000 23.100 ;
        RECT 29.400 22.200 30.600 28.200 ;
        RECT 29.400 1.800 30.600 4.800 ;
        RECT 29.700 1.800 30.600 6.600 ;
        RECT 29.700 5.700 32.100 6.000 ;
        RECT 29.700 5.700 30.900 6.600 ;
        RECT 31.800 22.200 33.000 28.200 ;
        RECT 31.800 1.800 33.000 4.800 ;
        RECT 31.200 15.900 33.600 17.100 ;
        RECT 34.500 12.000 35.400 28.200 ;
        RECT 34.200 22.200 35.400 28.200 ;
        RECT 34.200 1.800 35.400 4.800 ;
        RECT 34.500 1.800 35.400 9.000 ;
      LAYER via ;
        RECT 8.100 16.500 8.700 17.100 ;
        RECT 8.100 6.900 8.700 7.500 ;
        RECT 18.300 14.700 18.900 15.300 ;
        RECT 21.900 14.400 22.500 15.000 ;
        RECT 21.900 6.600 22.500 7.200 ;
        RECT 29.400 12.000 30.000 12.600 ;
        RECT 31.500 16.200 32.100 16.800 ;
  END 
END FAX1

MACRO HAX1
  CLASS  CORE ;
  FOREIGN HAX1 0.000 0.000 ;
  ORIGIN 0.000 0.000 ;
  SIZE 24.000 BY 30.000 ;
  SYMMETRY X Y  ;
  SITE core ;
  PIN YC
    DIRECTION OUTPUT ;
    PORT
      LAYER metal1 ;
        RECT 7.800 15.900 9.000 17.100 ;
    END
  END YC
  PIN YS
    DIRECTION OUTPUT ;
    PORT
      LAYER metal1 ;
        RECT 19.800 15.900 21.000 17.100 ;
    END
  END YS
  PIN A
    DIRECTION INPUT ;
    PORT
      LAYER metal1 ;
        RECT 0.600 9.900 1.800 11.100 ;
    END
  END A
  PIN B
    DIRECTION INPUT ;
    PORT
      LAYER metal1 ;
        RECT 3.000 12.900 4.200 14.100 ;
    END
  END B
  PIN gnd
    DIRECTION INOUT ;
    USE GROUND ;
    SHAPE ABUTMENT ;
    PORT
      LAYER metal1 ;
        RECT -0.600 -0.900 24.600 0.900 ;
    END
  END gnd
  PIN vdd
    DIRECTION INOUT ;
    USE POWER ;
    SHAPE ABUTMENT ;
    PORT
      LAYER metal1 ;
        RECT -0.600 29.100 24.600 30.900 ;
    END
  END vdd
  OBS 
      LAYER metal2 ;
        RECT 5.700 6.900 6.900 8.100 ;
        RECT 5.700 6.900 6.600 13.800 ;
        RECT 5.700 12.600 6.900 13.800 ;
        RECT 6.900 4.800 9.000 6.000 ;
        RECT 8.100 4.800 9.000 13.800 ;
        RECT 7.800 12.600 9.000 13.800 ;
      LAYER metal1 ;
        RECT 0.600 1.800 1.800 7.800 ;
        RECT 1.200 8.700 2.400 9.000 ;
        RECT 3.000 22.800 4.200 28.200 ;
        RECT 5.700 12.600 6.900 13.800 ;
        RECT 0.900 21.000 6.600 21.900 ;
        RECT 0.900 21.000 1.800 28.200 ;
        RECT 0.600 22.200 1.800 28.200 ;
        RECT 5.700 12.600 6.600 28.200 ;
        RECT 5.400 21.000 6.600 28.200 ;
        RECT 6.900 1.800 8.100 6.000 ;
        RECT 4.500 1.800 5.700 7.800 ;
        RECT 5.700 6.900 8.400 8.100 ;
        RECT 7.800 18.000 9.000 28.200 ;
        RECT 7.800 12.600 9.000 15.000 ;
        RECT 9.300 1.800 10.500 7.500 ;
        RECT 10.200 22.200 11.400 28.200 ;
        RECT 3.600 10.800 11.700 11.700 ;
        RECT 3.600 10.800 4.800 12.000 ;
        RECT 10.800 11.700 13.800 12.600 ;
        RECT 12.600 11.700 13.800 12.900 ;
        RECT 2.700 9.000 13.500 9.900 ;
        RECT 12.600 9.900 16.200 10.800 ;
        RECT 15.000 9.900 16.200 11.100 ;
        RECT 16.500 16.200 17.700 28.200 ;
        RECT 11.700 1.800 17.700 2.700 ;
        RECT 16.500 1.800 17.700 7.200 ;
        RECT 11.700 1.800 12.900 7.800 ;
        RECT 14.100 3.600 15.300 7.800 ;
        RECT 14.400 3.600 15.300 9.000 ;
        RECT 14.400 8.100 18.900 9.000 ;
        RECT 17.100 8.100 18.900 9.300 ;
        RECT 17.100 8.100 18.000 15.300 ;
        RECT 12.900 14.400 18.000 15.300 ;
        RECT 12.900 14.400 13.800 28.200 ;
        RECT 12.600 16.200 13.800 28.200 ;
        RECT 18.900 22.200 20.100 28.200 ;
        RECT 18.900 1.800 20.100 4.800 ;
        RECT 20.100 18.000 21.000 21.300 ;
        RECT 20.100 20.400 22.500 21.300 ;
        RECT 21.600 20.400 22.500 28.200 ;
        RECT 21.300 22.200 22.500 28.200 ;
        RECT 21.300 1.800 22.500 4.800 ;
        RECT 21.600 1.800 22.500 6.900 ;
        RECT 20.100 6.000 22.500 6.900 ;
        RECT 20.100 6.000 21.000 15.000 ;
      LAYER via ;
        RECT 6.000 12.900 6.600 13.500 ;
        RECT 6.000 7.200 6.600 7.800 ;
        RECT 7.200 5.100 7.800 5.700 ;
        RECT 8.100 12.900 8.700 13.500 ;
  END 
END HAX1

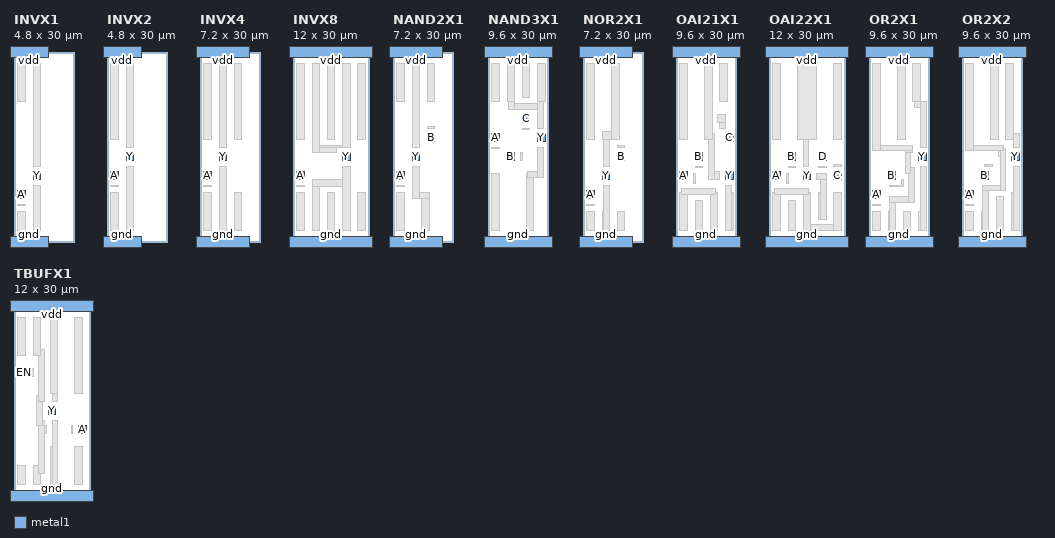
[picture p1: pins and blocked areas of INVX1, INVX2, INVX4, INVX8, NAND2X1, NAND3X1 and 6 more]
MACRO INVX1
  CLASS  CORE ;
  FOREIGN INVX1 0.000 0.000 ;
  ORIGIN 0.000 0.000 ;
  SIZE 4.800 BY 30.000 ;
  SYMMETRY X Y  ;
  SITE core ;
  PIN A
    DIRECTION INPUT ;
    PORT
      LAYER metal1 ;
        RECT 0.600 6.900 1.800 8.100 ;
    END
  END A
  PIN gnd
    DIRECTION INOUT ;
    USE GROUND ;
    SHAPE ABUTMENT ;
    PORT
      LAYER metal1 ;
        RECT -0.600 -0.900 5.400 0.900 ;
    END
  END gnd
  PIN Y
    DIRECTION OUTPUT ;
    PORT
      LAYER metal1 ;
        RECT 3.000 9.900 4.200 11.100 ;
    END
  END Y
  PIN vdd
    DIRECTION INOUT ;
    USE POWER ;
    SHAPE ABUTMENT ;
    PORT
      LAYER metal1 ;
        RECT -0.600 29.100 5.400 30.900 ;
    END
  END vdd
  OBS 
      LAYER metal1 ;
        RECT 0.600 22.200 1.800 28.200 ;
        RECT 0.600 5.700 1.800 6.000 ;
        RECT 0.600 1.800 1.800 4.800 ;
        RECT 3.000 12.000 4.200 28.200 ;
        RECT 3.000 1.800 4.200 9.000 ;
  END 
END INVX1

MACRO INVX2
  CLASS  CORE ;
  FOREIGN INVX2 0.000 0.000 ;
  ORIGIN 0.000 0.000 ;
  SIZE 4.800 BY 30.000 ;
  SYMMETRY X Y  ;
  SITE core ;
  PIN A
    DIRECTION INPUT ;
    PORT
      LAYER metal1 ;
        RECT 0.600 9.900 1.800 11.100 ;
    END
  END A
  PIN gnd
    DIRECTION INOUT ;
    USE GROUND ;
    SHAPE ABUTMENT ;
    PORT
      LAYER metal1 ;
        RECT -0.600 -0.900 5.400 0.900 ;
    END
  END gnd
  PIN Y
    DIRECTION OUTPUT ;
    PORT
      LAYER metal1 ;
        RECT 3.000 12.900 4.200 14.100 ;
    END
  END Y
  PIN vdd
    DIRECTION INOUT ;
    USE POWER ;
    SHAPE ABUTMENT ;
    PORT
      LAYER metal1 ;
        RECT -0.600 29.100 5.400 30.900 ;
    END
  END vdd
  OBS 
      LAYER metal1 ;
        RECT 0.600 16.200 1.800 28.200 ;
        RECT 0.600 8.700 1.800 9.000 ;
        RECT 0.600 1.800 1.800 7.800 ;
        RECT 3.000 15.000 4.200 28.200 ;
        RECT 3.000 1.800 4.200 12.000 ;
  END 
END INVX2

MACRO INVX4
  CLASS  CORE ;
  FOREIGN INVX4 0.000 0.000 ;
  ORIGIN 0.000 0.000 ;
  SIZE 7.200 BY 30.000 ;
  SYMMETRY X Y  ;
  SITE core ;
  PIN A
    DIRECTION INPUT ;
    PORT
      LAYER metal1 ;
        RECT 0.600 9.900 1.800 11.100 ;
    END
  END A
  PIN gnd
    DIRECTION INOUT ;
    USE GROUND ;
    SHAPE ABUTMENT ;
    PORT
      LAYER metal1 ;
        RECT -0.600 -0.900 7.800 0.900 ;
    END
  END gnd
  PIN Y
    DIRECTION OUTPUT ;
    PORT
      LAYER metal1 ;
        RECT 3.000 12.900 4.200 14.100 ;
    END
  END Y
  PIN vdd
    DIRECTION INOUT ;
    USE POWER ;
    SHAPE ABUTMENT ;
    PORT
      LAYER metal1 ;
        RECT -0.600 29.100 7.800 30.900 ;
    END
  END vdd
  OBS 
      LAYER metal1 ;
        RECT 0.600 16.200 1.800 28.200 ;
        RECT 0.600 8.700 1.800 9.000 ;
        RECT 0.600 1.800 1.800 7.800 ;
        RECT 3.000 15.000 4.200 28.200 ;
        RECT 3.000 1.800 4.200 12.000 ;
        RECT 5.400 16.200 6.600 28.200 ;
        RECT 5.400 1.800 6.600 7.800 ;
  END 
END INVX4

MACRO INVX8
  CLASS  CORE ;
  FOREIGN INVX8 0.000 0.000 ;
  ORIGIN 0.000 0.000 ;
  SIZE 12.000 BY 30.000 ;
  SYMMETRY X Y  ;
  SITE core ;
  PIN A
    DIRECTION INPUT ;
    PORT
      LAYER metal1 ;
        RECT 0.600 9.900 1.800 11.100 ;
    END
  END A
  PIN gnd
    DIRECTION INOUT ;
    USE GROUND ;
    SHAPE ABUTMENT ;
    PORT
      LAYER metal1 ;
        RECT -0.600 -0.900 12.600 0.900 ;
    END
  END gnd
  PIN Y
    DIRECTION OUTPUT ;
    PORT
      LAYER metal1 ;
        RECT 7.800 12.900 9.000 14.100 ;
    END
  END Y
  PIN vdd
    DIRECTION INOUT ;
    USE POWER ;
    SHAPE ABUTMENT ;
    PORT
      LAYER metal1 ;
        RECT -0.600 29.100 12.600 30.900 ;
    END
  END vdd
  OBS 
      LAYER metal1 ;
        RECT 0.600 16.200 1.800 28.200 ;
        RECT 0.600 8.700 1.800 9.000 ;
        RECT 0.600 1.800 1.800 7.800 ;
        RECT 5.400 16.200 6.600 28.200 ;
        RECT 5.400 1.800 6.600 7.800 ;
        RECT 3.000 14.100 6.900 15.300 ;
        RECT 3.000 15.000 9.000 15.300 ;
        RECT 3.000 14.100 4.200 28.200 ;
        RECT 7.800 15.000 9.000 28.200 ;
        RECT 3.000 1.800 4.200 9.900 ;
        RECT 3.000 8.700 9.000 9.900 ;
        RECT 7.800 1.800 9.000 12.000 ;
        RECT 10.200 16.200 11.400 28.200 ;
        RECT 10.200 1.800 11.400 7.800 ;
  END 
END INVX8

MACRO NAND2X1
  CLASS  CORE ;
  FOREIGN NAND2X1 0.000 0.000 ;
  ORIGIN 0.000 0.000 ;
  SIZE 7.200 BY 30.000 ;
  SYMMETRY X Y  ;
  SITE core ;
  PIN A
    DIRECTION INPUT ;
    PORT
      LAYER metal1 ;
        RECT 0.600 9.900 1.800 11.100 ;
    END
  END A
  PIN B
    DIRECTION INPUT ;
    PORT
      LAYER metal1 ;
        RECT 5.400 15.900 6.600 17.100 ;
    END
  END B
  PIN gnd
    DIRECTION INOUT ;
    USE GROUND ;
    SHAPE ABUTMENT ;
    PORT
      LAYER metal1 ;
        RECT -0.600 -0.900 7.800 0.900 ;
    END
  END gnd
  PIN Y
    DIRECTION OUTPUT ;
    PORT
      LAYER metal1 ;
        RECT 3.000 12.900 4.200 14.100 ;
    END
  END Y
  PIN vdd
    DIRECTION INOUT ;
    USE POWER ;
    SHAPE ABUTMENT ;
    PORT
      LAYER metal1 ;
        RECT -0.600 29.100 7.800 30.900 ;
    END
  END vdd
  OBS 
      LAYER metal1 ;
        RECT 0.600 22.200 1.800 28.200 ;
        RECT 0.600 8.700 1.800 9.000 ;
        RECT 0.600 1.800 1.800 7.800 ;
        RECT 3.000 15.000 4.200 28.200 ;
        RECT 4.500 1.800 5.700 7.800 ;
        RECT 3.000 6.900 5.700 7.800 ;
        RECT 3.000 6.900 4.200 12.000 ;
        RECT 5.400 22.200 6.600 28.200 ;
        RECT 5.400 18.000 6.600 18.300 ;
  END 
END NAND2X1

MACRO NAND3X1
  CLASS  CORE ;
  FOREIGN NAND3X1 0.000 0.000 ;
  ORIGIN 0.000 0.000 ;
  SIZE 9.600 BY 30.000 ;
  SYMMETRY X Y  ;
  SITE core ;
  PIN A
    DIRECTION INPUT ;
    PORT
      LAYER metal1 ;
        RECT 0.600 15.900 1.800 17.100 ;
    END
  END A
  PIN B
    DIRECTION INPUT ;
    PORT
      LAYER metal1 ;
        RECT 3.000 12.900 4.200 14.100 ;
    END
  END B
  PIN C
    DIRECTION INPUT ;
    PORT
      LAYER metal1 ;
        RECT 5.400 18.900 6.600 20.100 ;
    END
  END C
  PIN gnd
    DIRECTION INOUT ;
    USE GROUND ;
    SHAPE ABUTMENT ;
    PORT
      LAYER metal1 ;
        RECT -0.600 -0.900 10.200 0.900 ;
    END
  END gnd
  PIN Y
    DIRECTION OUTPUT ;
    PORT
      LAYER metal1 ;
        RECT 7.800 15.900 9.000 17.100 ;
    END
  END Y
  PIN vdd
    DIRECTION INOUT ;
    USE POWER ;
    SHAPE ABUTMENT ;
    PORT
      LAYER metal1 ;
        RECT -0.600 29.100 10.200 30.900 ;
    END
  END vdd
  OBS 
      LAYER metal1 ;
        RECT 0.600 22.200 1.800 28.200 ;
        RECT 0.600 14.700 1.800 15.000 ;
        RECT 0.600 1.800 1.800 10.800 ;
        RECT 5.100 12.900 5.400 14.100 ;
        RECT 5.400 22.800 6.600 28.200 ;
        RECT 5.400 17.700 6.600 18.000 ;
        RECT 6.000 1.800 7.200 10.800 ;
        RECT 6.300 10.200 8.700 11.100 ;
        RECT 7.800 10.200 8.700 15.000 ;
        RECT 3.300 21.000 8.700 21.900 ;
        RECT 7.800 18.000 8.700 28.200 ;
        RECT 3.300 21.000 4.200 28.200 ;
        RECT 3.000 22.200 4.200 28.200 ;
        RECT 7.800 22.200 9.000 28.200 ;
  END 
END NAND3X1

MACRO NOR2X1
  CLASS  CORE ;
  FOREIGN NOR2X1 0.000 0.000 ;
  ORIGIN 0.000 0.000 ;
  SIZE 7.200 BY 30.000 ;
  SYMMETRY X Y  ;
  SITE core ;
  PIN A
    DIRECTION INPUT ;
    PORT
      LAYER metal1 ;
        RECT 0.600 6.900 1.800 8.100 ;
    END
  END A
  PIN B
    DIRECTION INPUT ;
    PORT
      LAYER metal1 ;
        RECT 5.400 12.900 6.600 14.100 ;
    END
  END B
  PIN gnd
    DIRECTION INOUT ;
    USE GROUND ;
    SHAPE ABUTMENT ;
    PORT
      LAYER metal1 ;
        RECT -0.600 -0.900 7.800 0.900 ;
    END
  END gnd
  PIN Y
    DIRECTION OUTPUT ;
    PORT
      LAYER metal1 ;
        RECT 3.000 9.900 4.200 11.100 ;
    END
  END Y
  PIN vdd
    DIRECTION INOUT ;
    USE POWER ;
    SHAPE ABUTMENT ;
    PORT
      LAYER metal1 ;
        RECT -0.600 29.100 7.800 30.900 ;
    END
  END vdd
  OBS 
      LAYER metal1 ;
        RECT 0.600 16.200 1.800 28.200 ;
        RECT 0.600 5.700 1.800 6.000 ;
        RECT 0.600 1.800 1.800 4.800 ;
        RECT 3.000 1.800 4.200 4.800 ;
        RECT 3.300 1.800 4.200 9.000 ;
        RECT 3.300 12.000 4.200 17.400 ;
        RECT 3.000 16.200 5.700 17.400 ;
        RECT 4.500 16.200 5.700 28.200 ;
        RECT 5.400 15.000 6.600 15.300 ;
        RECT 5.400 1.800 6.600 4.800 ;
  END 
END NOR2X1

MACRO OAI21X1
  CLASS  CORE ;
  FOREIGN OAI21X1 0.000 0.000 ;
  ORIGIN 0.000 0.000 ;
  SIZE 9.600 BY 30.000 ;
  SYMMETRY X Y  ;
  SITE core ;
  PIN A
    DIRECTION INPUT ;
    PORT
      LAYER metal1 ;
        RECT 0.600 9.900 1.800 11.100 ;
    END
  END A
  PIN B
    DIRECTION INPUT ;
    PORT
      LAYER metal1 ;
        RECT 3.000 12.900 4.200 14.100 ;
    END
  END B
  PIN C
    DIRECTION INPUT ;
    PORT
      LAYER metal1 ;
        RECT 7.800 15.900 9.000 17.100 ;
    END
  END C
  PIN gnd
    DIRECTION INOUT ;
    USE GROUND ;
    SHAPE ABUTMENT ;
    PORT
      LAYER metal1 ;
        RECT -0.600 -0.900 10.200 0.900 ;
    END
  END gnd
  PIN Y
    DIRECTION OUTPUT ;
    PORT
      LAYER metal1 ;
        RECT 7.800 9.900 9.000 11.100 ;
    END
  END Y
  PIN vdd
    DIRECTION INOUT ;
    USE POWER ;
    SHAPE ABUTMENT ;
    PORT
      LAYER metal1 ;
        RECT -0.600 29.100 10.200 30.900 ;
    END
  END vdd
  OBS 
      LAYER metal1 ;
        RECT 0.600 16.200 1.800 28.200 ;
        RECT 2.700 9.300 3.000 10.800 ;
        RECT 3.000 11.700 4.200 12.000 ;
        RECT 3.000 1.800 4.200 6.600 ;
        RECT 0.600 1.800 1.800 7.800 ;
        RECT 5.400 1.800 6.600 7.800 ;
        RECT 0.900 7.500 6.300 8.400 ;
        RECT 5.100 9.900 6.900 11.100 ;
        RECT 5.100 9.900 6.000 17.100 ;
        RECT 4.500 16.200 5.700 28.200 ;
        RECT 6.900 18.000 7.800 20.100 ;
        RECT 6.600 18.900 7.800 20.100 ;
        RECT 6.900 22.200 8.100 28.200 ;
        RECT 7.800 1.800 9.000 7.800 ;
        RECT 7.800 1.800 8.700 9.000 ;
  END 
END OAI21X1

MACRO OAI22X1
  CLASS  CORE ;
  FOREIGN OAI22X1 0.000 0.000 ;
  ORIGIN 0.000 0.000 ;
  SIZE 12.000 BY 30.000 ;
  SYMMETRY X Y  ;
  SITE core ;
  PIN A
    DIRECTION INPUT ;
    PORT
      LAYER metal1 ;
        RECT 0.600 9.900 1.800 11.100 ;
    END
  END A
  PIN B
    DIRECTION INPUT ;
    PORT
      LAYER metal1 ;
        RECT 3.000 12.900 4.200 14.100 ;
    END
  END B
  PIN C
    DIRECTION INPUT ;
    PORT
      LAYER metal1 ;
        RECT 10.200 9.900 11.400 11.100 ;
    END
  END C
  PIN D
    DIRECTION INPUT ;
    PORT
      LAYER metal1 ;
        RECT 7.800 12.900 9.000 14.100 ;
    END
  END D
  PIN gnd
    DIRECTION INOUT ;
    USE GROUND ;
    SHAPE ABUTMENT ;
    PORT
      LAYER metal1 ;
        RECT -0.600 -0.900 12.600 0.900 ;
    END
  END gnd
  PIN Y
    DIRECTION OUTPUT ;
    PORT
      LAYER metal1 ;
        RECT 5.400 9.900 6.600 11.100 ;
    END
  END Y
  PIN vdd
    DIRECTION INOUT ;
    USE POWER ;
    SHAPE ABUTMENT ;
    PORT
      LAYER metal1 ;
        RECT -0.600 29.100 12.600 30.900 ;
    END
  END vdd
  OBS 
      LAYER metal1 ;
        RECT 0.600 16.200 1.800 28.200 ;
        RECT 2.700 9.300 3.000 10.800 ;
        RECT 3.000 11.700 4.200 12.000 ;
        RECT 3.000 1.800 4.200 6.600 ;
        RECT 5.400 12.000 6.300 28.200 ;
        RECT 4.500 16.200 7.500 28.200 ;
        RECT 7.800 11.700 9.000 12.000 ;
        RECT 7.800 3.600 9.000 7.800 ;
        RECT 8.100 3.600 9.000 10.800 ;
        RECT 7.500 9.900 9.000 10.800 ;
        RECT 10.200 16.200 11.400 28.200 ;
        RECT 10.200 12.000 11.400 12.300 ;
        RECT 5.400 1.800 11.400 2.700 ;
        RECT 0.600 1.800 1.800 7.800 ;
        RECT 5.400 1.800 6.600 7.800 ;
        RECT 10.200 1.800 11.400 7.800 ;
        RECT 0.900 7.500 6.300 8.400 ;
  END 
END OAI22X1

MACRO OR2X1
  CLASS  CORE ;
  FOREIGN OR2X1 0.000 0.000 ;
  ORIGIN 0.000 0.000 ;
  SIZE 9.600 BY 30.000 ;
  SYMMETRY X Y  ;
  SITE core ;
  PIN A
    DIRECTION INPUT ;
    PORT
      LAYER metal1 ;
        RECT 0.600 6.900 1.800 8.100 ;
    END
  END A
  PIN B
    DIRECTION INPUT ;
    PORT
      LAYER metal1 ;
        RECT 3.000 9.900 4.200 11.100 ;
    END
  END B
  PIN gnd
    DIRECTION INOUT ;
    USE GROUND ;
    SHAPE ABUTMENT ;
    PORT
      LAYER metal1 ;
        RECT -0.600 -0.900 10.200 0.900 ;
    END
  END gnd
  PIN Y
    DIRECTION OUTPUT ;
    PORT
      LAYER metal1 ;
        RECT 7.800 12.900 9.000 14.100 ;
    END
  END Y
  PIN vdd
    DIRECTION INOUT ;
    USE POWER ;
    SHAPE ABUTMENT ;
    PORT
      LAYER metal1 ;
        RECT -0.600 29.100 10.200 30.900 ;
    END
  END vdd
  OBS 
      LAYER metal1 ;
        RECT 0.600 5.700 1.800 6.000 ;
        RECT 0.600 1.800 1.800 4.800 ;
        RECT 3.300 8.700 5.400 9.000 ;
        RECT 5.100 8.700 5.400 9.900 ;
        RECT 4.500 16.200 5.700 28.200 ;
        RECT 5.400 1.800 6.600 4.800 ;
        RECT 3.000 1.800 4.200 4.800 ;
        RECT 3.300 1.800 4.200 7.200 ;
        RECT 3.300 6.300 7.200 7.200 ;
        RECT 6.300 6.300 7.200 11.700 ;
        RECT 5.700 10.800 6.600 15.300 ;
        RECT 5.700 14.100 6.900 15.300 ;
        RECT 0.600 14.400 6.900 15.300 ;
        RECT 0.600 14.400 1.800 28.200 ;
        RECT 7.200 21.300 9.000 22.200 ;
        RECT 8.100 15.000 9.000 22.200 ;
        RECT 6.900 22.200 8.100 28.200 ;
        RECT 7.800 1.800 9.000 4.800 ;
        RECT 8.100 1.800 9.000 12.000 ;
  END 
END OR2X1

MACRO OR2X2
  CLASS  CORE ;
  FOREIGN OR2X2 0.000 0.000 ;
  ORIGIN 0.000 0.000 ;
  SIZE 9.600 BY 30.000 ;
  SYMMETRY X Y  ;
  SITE core ;
  PIN A
    DIRECTION INPUT ;
    PORT
      LAYER metal1 ;
        RECT 0.600 6.900 1.800 8.100 ;
    END
  END A
  PIN B
    DIRECTION INPUT ;
    PORT
      LAYER metal1 ;
        RECT 3.000 9.900 4.200 11.100 ;
    END
  END B
  PIN gnd
    DIRECTION INOUT ;
    USE GROUND ;
    SHAPE ABUTMENT ;
    PORT
      LAYER metal1 ;
        RECT -0.600 -0.900 10.200 0.900 ;
    END
  END gnd
  PIN Y
    DIRECTION OUTPUT ;
    PORT
      LAYER metal1 ;
        RECT 7.800 12.900 9.000 14.100 ;
    END
  END Y
  PIN vdd
    DIRECTION INOUT ;
    USE POWER ;
    SHAPE ABUTMENT ;
    PORT
      LAYER metal1 ;
        RECT -0.600 29.100 10.200 30.900 ;
    END
  END vdd
  OBS 
      LAYER metal1 ;
        RECT 0.600 5.700 1.800 6.000 ;
        RECT 0.600 1.800 1.800 4.800 ;
        RECT 3.600 12.000 4.800 12.300 ;
        RECT 4.500 16.200 5.700 28.200 ;
        RECT 5.400 1.800 6.600 7.200 ;
        RECT 3.000 1.800 4.200 4.800 ;
        RECT 3.300 1.800 4.200 9.000 ;
        RECT 3.300 8.100 6.900 9.000 ;
        RECT 5.700 13.500 6.900 14.700 ;
        RECT 6.000 8.100 6.900 14.700 ;
        RECT 0.600 14.400 6.600 15.300 ;
        RECT 0.600 14.400 1.800 28.200 ;
        RECT 8.100 15.000 9.000 17.100 ;
        RECT 6.900 16.200 8.100 28.200 ;
        RECT 7.800 1.800 9.000 7.800 ;
        RECT 8.100 1.800 9.000 12.000 ;
  END 
END OR2X2

MACRO TBUFX1
  CLASS  CORE ;
  FOREIGN TBUFX1 0.000 0.000 ;
  ORIGIN 0.000 0.000 ;
  SIZE 12.000 BY 30.000 ;
  SYMMETRY X Y  ;
  SITE core ;
  PIN A
    DIRECTION INPUT ;
    PORT
      LAYER metal1 ;
        RECT 10.200 9.900 11.400 11.100 ;
    END
  END A
  PIN EN
    DIRECTION INPUT ;
    PORT
      LAYER metal1 ;
        RECT 0.600 18.900 1.800 20.100 ;
    END
  END EN
  PIN gnd
    DIRECTION INOUT ;
    USE GROUND ;
    SHAPE ABUTMENT ;
    PORT
      LAYER metal1 ;
        RECT -0.600 -0.900 12.600 0.900 ;
    END
  END gnd
  PIN Y
    DIRECTION OUTPUT ;
    PORT
      LAYER metal1 ;
        RECT 5.400 12.900 6.600 14.100 ;
    END
  END Y
  PIN vdd
    DIRECTION INOUT ;
    USE POWER ;
    SHAPE ABUTMENT ;
    PORT
      LAYER metal1 ;
        RECT -0.600 29.100 12.600 30.900 ;
    END
  END vdd
  OBS 
      LAYER metal1 ;
        RECT 0.600 22.200 1.800 28.200 ;
        RECT 0.600 1.800 1.800 4.800 ;
        RECT 2.700 18.900 3.000 20.100 ;
        RECT 3.000 1.800 4.200 4.800 ;
        RECT 3.900 9.900 5.100 11.100 ;
        RECT 3.900 3.600 4.800 12.000 ;
        RECT 3.600 11.100 4.500 15.900 ;
        RECT 3.900 15.000 4.800 23.100 ;
        RECT 3.000 22.200 4.200 28.200 ;
        RECT 6.000 15.000 6.900 28.200 ;
        RECT 5.700 16.200 6.900 28.200 ;
        RECT 5.700 1.800 6.900 7.800 ;
        RECT 6.000 1.800 6.900 12.000 ;
        RECT 9.000 9.900 9.300 11.100 ;
        RECT 9.600 16.200 10.800 28.200 ;
        RECT 9.600 1.800 10.800 7.800 ;
  END 
END TBUFX1

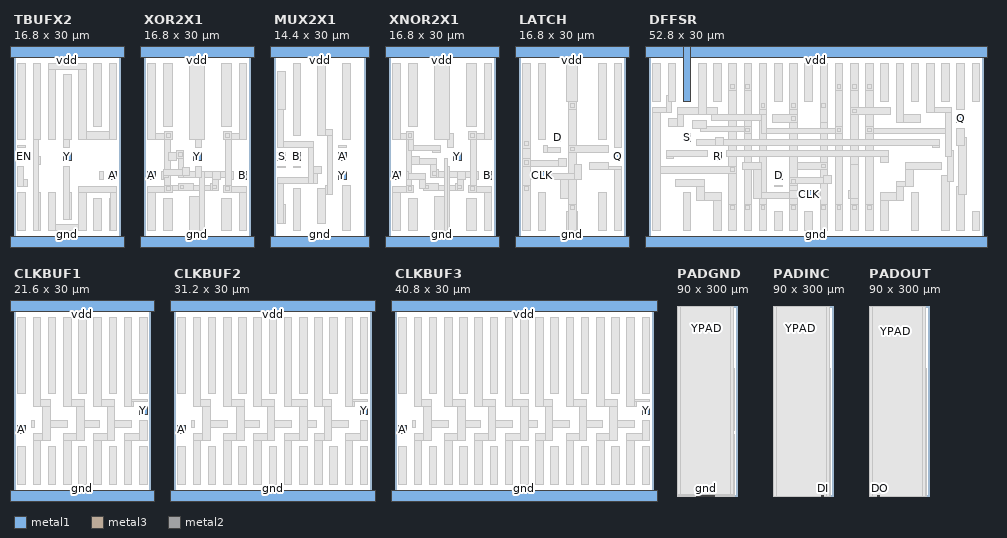
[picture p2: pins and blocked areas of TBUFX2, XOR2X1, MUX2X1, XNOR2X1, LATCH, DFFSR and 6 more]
MACRO TBUFX2
  CLASS  CORE ;
  FOREIGN TBUFX2 0.000 0.000 ;
  ORIGIN 0.000 0.000 ;
  SIZE 16.800 BY 30.000 ;
  SYMMETRY X Y  ;
  SITE core ;
  PIN A
    DIRECTION INPUT ;
    PORT
      LAYER metal1 ;
        RECT 15.000 9.900 16.200 11.100 ;
    END
  END A
  PIN EN
    DIRECTION INPUT ;
    PORT
      LAYER metal1 ;
        RECT 0.600 12.900 1.800 14.100 ;
    END
  END EN
  PIN gnd
    DIRECTION INOUT ;
    USE GROUND ;
    SHAPE ABUTMENT ;
    PORT
      LAYER metal1 ;
        RECT -0.600 -0.900 17.400 0.900 ;
    END
  END gnd
  PIN Y
    DIRECTION OUTPUT ;
    PORT
      LAYER metal1 ;
        RECT 7.800 12.900 9.000 14.100 ;
    END
  END Y
  PIN vdd
    DIRECTION INOUT ;
    USE POWER ;
    SHAPE ABUTMENT ;
    PORT
      LAYER metal1 ;
        RECT -0.600 29.100 17.400 30.900 ;
    END
  END vdd
  OBS 
      LAYER metal1 ;
        RECT 0.600 16.200 1.800 28.200 ;
        RECT 0.600 15.000 1.800 15.300 ;
        RECT 0.600 1.800 1.800 7.800 ;
        RECT 0.600 8.700 2.100 9.900 ;
        RECT 0.600 8.700 1.500 12.000 ;
        RECT 3.000 1.800 4.200 7.800 ;
        RECT 3.000 12.300 4.200 13.500 ;
        RECT 3.000 1.800 3.900 28.200 ;
        RECT 3.000 16.200 4.200 28.200 ;
        RECT 7.800 15.000 8.700 26.400 ;
        RECT 7.800 16.200 9.000 26.400 ;
        RECT 7.800 3.600 9.000 7.800 ;
        RECT 7.800 3.600 8.700 12.000 ;
        RECT 12.600 18.300 13.800 28.200 ;
        RECT 12.600 1.800 13.800 6.900 ;
        RECT 13.500 9.900 14.100 11.100 ;
        RECT 10.200 16.200 16.200 17.400 ;
        RECT 5.400 16.200 6.600 28.200 ;
        RECT 10.200 16.200 11.400 28.200 ;
        RECT 5.400 27.300 11.400 28.200 ;
        RECT 15.000 16.200 16.200 28.200 ;
        RECT 5.400 1.800 11.400 2.700 ;
        RECT 15.000 1.800 16.200 6.900 ;
        RECT 10.200 1.800 11.400 8.700 ;
        RECT 5.400 1.800 6.600 7.800 ;
        RECT 15.300 1.800 16.200 8.700 ;
        RECT 10.200 7.800 16.200 8.700 ;
  END 
END TBUFX2

MACRO XOR2X1
  CLASS  CORE ;
  FOREIGN XOR2X1 0.000 0.000 ;
  ORIGIN 0.000 0.000 ;
  SIZE 16.800 BY 30.000 ;
  SYMMETRY X Y  ;
  SITE core ;
  PIN A
    DIRECTION INPUT ;
    PORT
      LAYER metal1 ;
        RECT 0.600 9.900 1.800 11.100 ;
    END
  END A
  PIN B
    DIRECTION INPUT ;
    PORT
      LAYER metal1 ;
        RECT 15.000 9.900 16.200 11.100 ;
    END
  END B
  PIN gnd
    DIRECTION INOUT ;
    USE GROUND ;
    SHAPE ABUTMENT ;
    PORT
      LAYER metal1 ;
        RECT -0.600 -0.900 17.400 0.900 ;
    END
  END gnd
  PIN Y
    DIRECTION OUTPUT ;
    PORT
      LAYER metal1 ;
        RECT 7.800 12.900 9.000 14.100 ;
    END
  END Y
  PIN vdd
    DIRECTION INOUT ;
    USE POWER ;
    SHAPE ABUTMENT ;
    PORT
      LAYER metal1 ;
        RECT -0.600 29.100 17.400 30.900 ;
    END
  END vdd
  OBS 
      LAYER metal2 ;
        RECT 3.300 7.800 4.500 9.000 ;
        RECT 3.300 8.100 11.700 9.000 ;
        RECT 5.400 8.100 6.600 9.300 ;
        RECT 10.500 8.100 11.700 9.300 ;
        RECT 3.300 7.800 4.200 17.400 ;
        RECT 3.300 16.200 4.500 17.400 ;
        RECT 12.600 7.800 13.800 9.000 ;
        RECT 5.400 10.200 13.800 11.100 ;
        RECT 5.400 10.200 6.300 14.400 ;
        RECT 5.100 13.200 6.300 14.400 ;
        RECT 12.900 7.800 13.800 17.400 ;
        RECT 12.600 16.200 13.800 17.400 ;
      LAYER metal1 ;
        RECT 3.000 18.300 4.500 28.200 ;
        RECT 0.600 16.200 4.500 17.100 ;
        RECT 3.300 16.200 4.500 17.400 ;
        RECT 0.600 16.200 1.800 28.200 ;
        RECT 0.600 1.800 1.800 8.700 ;
        RECT 0.600 7.800 4.500 8.700 ;
        RECT 3.300 7.800 4.500 9.000 ;
        RECT 3.000 1.800 4.500 6.900 ;
        RECT 3.900 12.900 5.100 14.100 ;
        RECT 5.100 13.200 6.300 14.400 ;
        RECT 2.700 10.200 3.900 11.100 ;
        RECT 2.700 9.900 3.000 11.100 ;
        RECT 3.000 10.500 7.200 11.400 ;
        RECT 6.000 10.500 7.200 11.700 ;
        RECT 5.400 8.100 7.800 9.300 ;
        RECT 8.100 15.000 9.000 28.200 ;
        RECT 7.200 16.200 9.600 28.200 ;
        RECT 7.200 1.800 9.600 7.200 ;
        RECT 8.700 1.800 9.600 11.100 ;
        RECT 8.100 10.200 9.000 12.000 ;
        RECT 10.500 8.100 11.700 9.300 ;
        RECT 10.800 8.100 11.700 11.100 ;
        RECT 10.800 9.900 12.000 11.100 ;
        RECT 12.300 18.300 13.800 28.200 ;
        RECT 12.300 1.800 13.800 6.900 ;
        RECT 13.800 9.900 14.100 11.100 ;
        RECT 12.600 16.200 16.200 17.100 ;
        RECT 12.600 16.200 13.800 17.400 ;
        RECT 15.000 16.200 16.200 28.200 ;
        RECT 15.000 1.800 16.200 8.700 ;
        RECT 12.600 7.800 16.200 8.700 ;
        RECT 12.600 7.800 13.800 9.000 ;
      LAYER via ;
        RECT 3.600 16.500 4.200 17.100 ;
        RECT 3.600 8.100 4.200 8.700 ;
        RECT 5.400 13.500 6.000 14.100 ;
        RECT 5.700 8.400 6.300 9.000 ;
        RECT 10.800 8.400 11.400 9.000 ;
        RECT 12.900 16.500 13.500 17.100 ;
        RECT 12.900 8.100 13.500 8.700 ;
  END 
END XOR2X1

MACRO MUX2X1
  CLASS  CORE ;
  FOREIGN MUX2X1 0.000 0.000 ;
  ORIGIN 0.000 0.000 ;
  SIZE 14.400 BY 30.000 ;
  SYMMETRY X Y  ;
  SITE core ;
  PIN A
    DIRECTION INPUT ;
    PORT
      LAYER metal1 ;
        RECT 10.200 12.900 11.400 14.100 ;
    END
  END A
  PIN B
    DIRECTION INPUT ;
    PORT
      LAYER metal1 ;
        RECT 3.000 12.900 4.200 14.100 ;
    END
  END B
  PIN S
    DIRECTION INPUT ;
    PORT
      LAYER metal1 ;
        RECT 0.600 12.900 1.800 14.100 ;
    END
  END S
  PIN gnd
    DIRECTION INOUT ;
    USE GROUND ;
    SHAPE ABUTMENT ;
    PORT
      LAYER metal1 ;
        RECT -0.600 -0.900 15.000 0.900 ;
    END
  END gnd
  PIN Y
    DIRECTION OUTPUT ;
    PORT
      LAYER metal1 ;
        RECT 10.200 9.900 11.400 11.100 ;
    END
  END Y
  PIN vdd
    DIRECTION INOUT ;
    USE POWER ;
    SHAPE ABUTMENT ;
    PORT
      LAYER metal1 ;
        RECT -0.600 29.100 15.000 30.900 ;
    END
  END vdd
  OBS 
      LAYER metal1 ;
        RECT 0.600 11.700 1.800 12.000 ;
        RECT 3.000 16.800 4.200 28.200 ;
        RECT 3.000 11.700 4.200 12.000 ;
        RECT 3.000 1.800 4.200 8.400 ;
        RECT 0.600 3.000 1.800 6.000 ;
        RECT 0.600 3.000 1.500 10.200 ;
        RECT 0.600 9.300 6.900 10.200 ;
        RECT 5.400 9.300 6.900 12.000 ;
        RECT 5.400 10.800 7.500 12.000 ;
        RECT 5.400 9.300 6.300 15.900 ;
        RECT 0.600 15.000 6.300 15.900 ;
        RECT 0.600 15.000 1.500 27.000 ;
        RECT 0.600 21.000 1.800 27.000 ;
        RECT 6.900 3.000 8.100 8.400 ;
        RECT 8.100 7.500 9.300 9.000 ;
        RECT 8.400 7.500 9.300 17.700 ;
        RECT 6.900 16.800 9.300 17.700 ;
        RECT 6.900 16.800 8.100 28.200 ;
        RECT 10.200 15.000 11.400 15.300 ;
        RECT 10.800 16.200 12.000 28.200 ;
        RECT 10.800 1.800 12.000 9.000 ;
  END 
END MUX2X1

MACRO XNOR2X1
  CLASS  CORE ;
  FOREIGN XNOR2X1 0.000 0.000 ;
  ORIGIN 0.000 0.000 ;
  SIZE 16.800 BY 30.000 ;
  SYMMETRY X Y  ;
  SITE core ;
  PIN A
    DIRECTION INPUT ;
    PORT
      LAYER metal1 ;
        RECT 0.600 9.900 1.800 11.100 ;
    END
  END A
  PIN B
    DIRECTION INPUT ;
    PORT
      LAYER metal1 ;
        RECT 15.000 9.900 16.200 11.100 ;
    END
  END B
  PIN gnd
    DIRECTION INOUT ;
    USE GROUND ;
    SHAPE ABUTMENT ;
    PORT
      LAYER metal1 ;
        RECT -0.600 -0.900 17.400 0.900 ;
    END
  END gnd
  PIN Y
    DIRECTION OUTPUT ;
    PORT
      LAYER metal1 ;
        RECT 10.200 12.900 11.400 14.100 ;
    END
  END Y
  PIN vdd
    DIRECTION INOUT ;
    USE POWER ;
    SHAPE ABUTMENT ;
    PORT
      LAYER metal1 ;
        RECT -0.600 29.100 17.400 30.900 ;
    END
  END vdd
  OBS 
      LAYER metal2 ;
        RECT 2.700 7.800 3.900 9.000 ;
        RECT 2.700 7.800 3.600 17.400 ;
        RECT 2.700 16.200 3.900 17.400 ;
        RECT 5.400 8.100 11.700 9.000 ;
        RECT 5.400 8.100 6.600 9.300 ;
        RECT 10.500 8.100 11.700 9.300 ;
        RECT 12.600 7.800 13.800 9.000 ;
        RECT 6.600 10.200 13.800 11.100 ;
        RECT 6.600 10.200 7.800 11.400 ;
        RECT 12.900 7.800 13.800 17.400 ;
        RECT 12.600 16.200 13.800 17.400 ;
      LAYER metal1 ;
        RECT 0.600 1.800 1.800 8.700 ;
        RECT 0.600 7.800 3.900 8.700 ;
        RECT 2.700 7.800 3.900 9.000 ;
        RECT 3.000 18.300 4.500 28.200 ;
        RECT 3.000 1.800 4.500 6.900 ;
        RECT 6.600 10.200 7.800 11.400 ;
        RECT 6.600 10.200 7.500 13.200 ;
        RECT 3.600 12.300 7.500 13.200 ;
        RECT 3.600 12.300 4.800 13.500 ;
        RECT 5.400 8.100 7.800 9.300 ;
        RECT 4.800 8.400 5.700 10.800 ;
        RECT 2.700 9.900 5.700 10.800 ;
        RECT 2.700 9.900 3.000 11.100 ;
        RECT 6.900 14.100 8.100 15.300 ;
        RECT 3.000 14.400 8.100 15.300 ;
        RECT 0.600 16.200 3.900 17.100 ;
        RECT 3.000 14.400 3.900 17.400 ;
        RECT 2.700 16.200 3.900 17.400 ;
        RECT 0.600 16.200 1.800 28.200 ;
        RECT 7.200 1.800 9.600 7.200 ;
        RECT 8.700 1.800 9.600 12.000 ;
        RECT 8.700 1.800 9.300 13.200 ;
        RECT 9.300 15.000 10.200 17.100 ;
        RECT 7.200 16.200 9.600 28.200 ;
        RECT 10.500 8.100 11.700 9.300 ;
        RECT 10.800 8.100 11.700 11.100 ;
        RECT 10.800 9.900 12.000 11.100 ;
        RECT 12.300 18.300 13.800 28.200 ;
        RECT 12.300 1.800 13.800 6.900 ;
        RECT 13.800 9.900 14.100 11.100 ;
        RECT 12.600 16.200 16.200 17.100 ;
        RECT 12.600 16.200 13.800 17.400 ;
        RECT 15.000 16.200 16.200 28.200 ;
        RECT 15.000 1.800 16.200 8.700 ;
        RECT 12.600 7.800 16.200 8.700 ;
        RECT 12.600 7.800 13.800 9.000 ;
      LAYER via ;
        RECT 3.000 16.500 3.600 17.100 ;
        RECT 3.000 8.100 3.600 8.700 ;
        RECT 5.700 8.400 6.300 9.000 ;
        RECT 6.900 10.500 7.500 11.100 ;
        RECT 10.800 8.400 11.400 9.000 ;
        RECT 12.900 16.500 13.500 17.100 ;
        RECT 12.900 8.100 13.500 8.700 ;
  END 
END XNOR2X1

MACRO LATCH
  CLASS  CORE ;
  FOREIGN LATCH 0.000 0.000 ;
  ORIGIN 0.000 0.000 ;
  SIZE 16.800 BY 30.000 ;
  SYMMETRY X Y  ;
  SITE core ;
  PIN Q
    DIRECTION OUTPUT ;
    PORT
      LAYER metal1 ;
        RECT 15.000 12.900 16.200 14.100 ;
    END
  END Q
  PIN CLK
    DIRECTION INPUT ;
    PORT
      LAYER metal1 ;
        RECT 3.000 9.900 4.200 11.100 ;
    END
  END CLK
  PIN D
    DIRECTION INPUT ;
    PORT
      LAYER metal1 ;
        RECT 5.400 15.900 6.600 17.100 ;
    END
  END D
  PIN gnd
    DIRECTION INOUT ;
    USE GROUND ;
    SHAPE ABUTMENT ;
    PORT
      LAYER metal1 ;
        RECT -0.600 -0.900 17.400 0.900 ;
    END
  END gnd
  PIN vdd
    DIRECTION INOUT ;
    USE POWER ;
    SHAPE ABUTMENT ;
    PORT
      LAYER metal1 ;
        RECT -0.600 29.100 17.400 30.900 ;
    END
  END vdd
  OBS 
      LAYER metal2 ;
        RECT 0.600 7.800 1.800 16.200 ;
        RECT 7.800 4.800 9.000 22.200 ;
      LAYER metal1 ;
        RECT 0.600 14.700 1.800 28.200 ;
        RECT 0.600 1.800 1.800 9.000 ;
        RECT 1.800 9.900 2.100 11.100 ;
        RECT 3.000 16.200 4.200 28.200 ;
        RECT 3.000 1.800 4.200 7.800 ;
        RECT 3.900 14.100 6.600 15.000 ;
        RECT 3.900 14.100 4.500 15.300 ;
        RECT 0.600 12.000 7.500 12.900 ;
        RECT 0.600 12.000 1.800 13.200 ;
        RECT 6.300 12.000 7.500 13.200 ;
        RECT 7.800 21.000 9.000 28.200 ;
        RECT 7.500 22.200 9.300 28.200 ;
        RECT 7.500 1.800 9.300 4.800 ;
        RECT 7.800 1.800 9.000 6.000 ;
        RECT 6.600 6.900 7.800 10.800 ;
        RECT 5.100 9.900 9.900 10.800 ;
        RECT 8.700 9.900 9.900 12.300 ;
        RECT 12.600 16.200 13.800 28.200 ;
        RECT 12.600 1.800 13.800 7.800 ;
        RECT 7.800 14.100 14.100 15.300 ;
        RECT 15.000 15.000 16.200 28.200 ;
        RECT 15.000 1.800 16.200 12.000 ;
        RECT 11.100 11.400 16.200 12.000 ;
        RECT 11.100 11.400 14.100 12.600 ;
      LAYER via ;
        RECT 0.900 15.300 1.500 15.900 ;
        RECT 0.900 12.300 1.500 12.900 ;
        RECT 0.900 8.100 1.500 8.700 ;
        RECT 8.100 21.300 8.700 21.900 ;
        RECT 8.100 14.400 8.700 15.000 ;
        RECT 8.100 5.100 8.700 5.700 ;
  END 
END LATCH

MACRO DFFSR
  CLASS  CORE ;
  FOREIGN DFFSR 0.000 0.000 ;
  ORIGIN 0.000 0.000 ;
  SIZE 52.800 BY 30.000 ;
  SYMMETRY X Y  ;
  SITE core ;
  PIN Q
    DIRECTION OUTPUT ;
    PORT
      LAYER metal1 ;
        RECT 48.600 18.900 49.800 20.100 ;
    END
  END Q
  PIN CLK
    DIRECTION INPUT ;
    PORT
      LAYER metal1 ;
        RECT 24.600 6.900 25.800 8.100 ;
    END
  END CLK
  PIN R
    DIRECTION INPUT ;
    PORT
      LAYER metal1 ;
        RECT 10.200 12.900 11.400 14.100 ;
    END
  END R
  PIN S
    DIRECTION INPUT ;
    PORT
      LAYER metal1 ;
        RECT 5.400 15.900 6.600 17.100 ;
    END
  END S
  PIN D
    DIRECTION INPUT ;
    PORT
      LAYER metal1 ;
        RECT 19.800 9.900 21.000 11.100 ;
    END
  END D
  PIN gnd
    DIRECTION INOUT ;
    USE GROUND ;
    SHAPE ABUTMENT ;
    PORT
      LAYER metal1 ;
        RECT -0.600 -0.900 53.400 0.900 ;
    END
  END gnd
  PIN vdd
    DIRECTION INOUT ;
    USE POWER ;
    SHAPE ABUTMENT ;
    PORT
      LAYER metal1 ;
        RECT -0.600 29.100 53.400 30.900 ;
        RECT 5.400 22.200 6.600 30.900 ;
    END
  END vdd
  OBS 
      LAYER metal2 ;
        RECT 12.600 4.800 13.800 25.200 ;
        RECT 15.000 4.800 16.200 25.200 ;
        RECT 17.400 4.800 18.600 22.200 ;
        RECT 22.200 4.800 23.400 22.200 ;
        RECT 27.000 4.800 28.200 22.200 ;
        RECT 29.400 4.800 30.600 25.200 ;
        RECT 31.800 4.800 33.000 25.200 ;
        RECT 34.200 4.800 35.400 25.200 ;
      LAYER metal1 ;
        RECT 0.600 22.200 1.800 28.200 ;
        RECT 5.400 1.800 6.600 7.800 ;
        RECT 2.700 13.200 3.900 14.400 ;
        RECT 2.700 13.500 9.300 14.400 ;
        RECT 10.200 22.200 11.400 28.200 ;
        RECT 10.200 1.800 11.400 7.800 ;
        RECT 7.500 6.600 11.400 7.800 ;
        RECT 7.500 6.600 8.700 9.900 ;
        RECT 4.200 8.700 8.700 9.900 ;
        RECT 12.600 24.000 13.800 28.200 ;
        RECT 0.600 10.800 13.800 12.000 ;
        RECT 0.600 1.800 1.800 21.300 ;
        RECT 0.600 20.400 3.600 21.300 ;
        RECT 2.700 20.400 3.600 23.100 ;
        RECT 3.000 22.200 4.200 28.200 ;
        RECT 12.600 1.800 13.800 6.000 ;
        RECT 15.000 24.000 16.200 28.200 ;
        RECT 8.100 17.400 16.200 18.300 ;
        RECT 15.000 17.100 16.200 18.300 ;
        RECT 6.900 18.000 9.000 19.200 ;
        RECT 15.000 1.800 16.200 6.000 ;
        RECT 17.400 21.000 18.600 28.200 ;
        RECT 17.400 1.800 18.600 6.000 ;
        RECT 19.800 22.200 21.000 28.200 ;
        RECT 19.800 8.700 21.000 9.000 ;
        RECT 19.800 1.800 21.000 4.800 ;
        RECT 22.200 21.000 23.400 28.200 ;
        RECT 19.500 18.900 23.400 20.100 ;
        RECT 16.500 6.900 23.400 7.800 ;
        RECT 22.200 6.900 23.400 8.100 ;
        RECT 16.500 6.900 17.700 12.600 ;
        RECT 14.700 11.400 17.700 12.600 ;
        RECT 22.200 1.800 23.400 6.000 ;
        RECT 24.600 22.200 25.800 28.200 ;
        RECT 24.600 1.800 25.800 4.800 ;
        RECT 26.700 6.900 27.000 8.100 ;
        RECT 27.000 18.900 28.200 28.200 ;
        RECT 23.400 11.400 28.200 12.600 ;
        RECT 27.000 1.800 28.200 6.000 ;
        RECT 22.200 9.000 23.400 10.200 ;
        RECT 22.200 9.300 28.800 10.200 ;
        RECT 27.600 9.300 28.800 10.500 ;
        RECT 29.400 24.000 30.600 28.200 ;
        RECT 17.700 17.100 30.600 18.000 ;
        RECT 29.400 17.100 30.600 18.300 ;
        RECT 3.000 18.300 5.400 19.500 ;
        RECT 4.500 18.300 5.400 21.300 ;
        RECT 9.900 19.200 18.600 20.100 ;
        RECT 17.700 17.100 18.600 20.100 ;
        RECT 4.500 20.100 10.800 21.300 ;
        RECT 7.800 20.100 9.000 28.200 ;
        RECT 29.400 1.800 30.600 6.000 ;
        RECT 31.800 24.000 33.000 28.200 ;
        RECT 31.500 6.900 33.000 8.100 ;
        RECT 31.800 6.900 33.000 12.300 ;
        RECT 31.800 1.800 33.000 6.000 ;
        RECT 34.200 24.000 35.400 28.200 ;
        RECT 34.200 1.800 35.400 6.000 ;
        RECT 36.600 22.200 37.800 28.200 ;
        RECT 36.600 12.600 37.800 14.400 ;
        RECT 12.300 13.500 37.800 14.400 ;
        RECT 31.800 20.100 38.100 21.300 ;
        RECT 41.400 22.200 42.600 28.200 ;
        RECT 41.400 1.800 42.600 7.800 ;
        RECT 39.000 18.900 42.900 20.100 ;
        RECT 39.000 18.900 40.200 28.200 ;
        RECT 44.700 15.000 45.900 16.200 ;
        RECT 7.500 15.300 45.900 16.200 ;
        RECT 10.500 15.300 11.700 16.500 ;
        RECT 36.600 1.800 37.800 7.800 ;
        RECT 36.600 6.600 40.200 7.800 ;
        RECT 39.000 6.600 40.200 9.600 ;
        RECT 39.000 8.700 41.700 9.600 ;
        RECT 40.500 8.700 41.700 12.600 ;
        RECT 40.500 11.400 46.200 12.600 ;
        RECT 46.200 22.200 47.400 28.200 ;
        RECT 46.200 1.800 47.400 10.500 ;
        RECT 47.100 9.600 48.000 14.400 ;
        RECT 34.200 17.100 47.700 18.000 ;
        RECT 34.200 17.100 35.400 18.300 ;
        RECT 46.800 13.500 47.700 21.300 ;
        RECT 43.800 20.400 47.700 21.300 ;
        RECT 43.800 20.400 45.000 28.200 ;
        RECT 48.600 21.000 49.800 28.200 ;
        RECT 48.600 1.800 49.800 8.700 ;
        RECT 48.900 7.500 50.100 16.500 ;
        RECT 48.600 15.300 49.800 18.000 ;
        RECT 51.000 22.200 52.200 28.200 ;
        RECT 51.000 1.800 52.200 4.800 ;
      LAYER via ;
        RECT 12.900 24.300 13.500 24.900 ;
        RECT 12.900 11.100 13.500 11.700 ;
        RECT 12.900 5.100 13.500 5.700 ;
        RECT 15.300 24.300 15.900 24.900 ;
        RECT 15.300 17.400 15.900 18.000 ;
        RECT 15.300 5.100 15.900 5.700 ;
        RECT 17.700 21.300 18.300 21.900 ;
        RECT 17.700 5.100 18.300 5.700 ;
        RECT 22.500 21.300 23.100 21.900 ;
        RECT 22.500 19.200 23.100 19.800 ;
        RECT 22.500 9.300 23.100 9.900 ;
        RECT 22.500 5.100 23.100 5.700 ;
        RECT 27.300 21.300 27.900 21.900 ;
        RECT 27.300 11.700 27.900 12.300 ;
        RECT 27.300 5.100 27.900 5.700 ;
        RECT 29.700 24.300 30.300 24.900 ;
        RECT 29.700 17.400 30.300 18.000 ;
        RECT 29.700 5.100 30.300 5.700 ;
        RECT 32.100 24.300 32.700 24.900 ;
        RECT 32.100 20.400 32.700 21.000 ;
        RECT 32.100 5.100 32.700 5.700 ;
        RECT 34.500 24.300 35.100 24.900 ;
        RECT 34.500 17.400 35.100 18.000 ;
        RECT 34.500 5.100 35.100 5.700 ;
  END 
END DFFSR

MACRO CLKBUF1
  CLASS  CORE ;
  FOREIGN CLKBUF1 0.000 0.000 ;
  ORIGIN 0.000 0.000 ;
  SIZE 21.600 BY 30.000 ;
  SYMMETRY X Y  ;
  SITE core ;
  PIN A
    DIRECTION INPUT ;
    PORT
      LAYER metal1 ;
        RECT 0.600 9.900 1.800 11.100 ;
    END
  END A
  PIN gnd
    DIRECTION INOUT ;
    USE GROUND ;
    SHAPE ABUTMENT ;
    PORT
      LAYER metal1 ;
        RECT -0.600 -0.900 22.200 0.900 ;
    END
  END gnd
  PIN Y
    DIRECTION OUTPUT ;
    PORT
      LAYER metal1 ;
        RECT 19.800 12.900 21.000 14.100 ;
    END
  END Y
  PIN vdd
    DIRECTION INOUT ;
    USE POWER ;
    SHAPE ABUTMENT ;
    PORT
      LAYER metal1 ;
        RECT -0.600 29.100 22.200 30.900 ;
    END
  END vdd
  OBS 
      LAYER metal1 ;
        RECT 0.600 16.200 1.800 28.200 ;
        RECT 0.600 1.800 1.800 7.800 ;
        RECT 2.700 10.800 3.300 12.000 ;
        RECT 5.400 16.200 6.600 28.200 ;
        RECT 5.400 1.800 6.600 7.800 ;
        RECT 3.000 1.800 4.200 9.900 ;
        RECT 3.000 8.700 5.700 9.900 ;
        RECT 4.500 10.800 8.400 12.000 ;
        RECT 4.500 8.700 5.700 15.300 ;
        RECT 3.000 14.100 5.700 15.300 ;
        RECT 3.000 14.100 4.200 28.200 ;
        RECT 10.200 16.200 11.400 28.200 ;
        RECT 10.200 1.800 11.400 7.800 ;
        RECT 7.800 1.800 9.000 9.900 ;
        RECT 7.800 8.700 11.100 9.900 ;
        RECT 9.900 10.800 13.500 12.000 ;
        RECT 9.900 8.700 11.100 15.300 ;
        RECT 7.800 14.100 11.100 15.300 ;
        RECT 7.800 14.100 9.000 28.200 ;
        RECT 15.000 16.200 16.200 28.200 ;
        RECT 15.000 1.800 16.200 7.800 ;
        RECT 12.600 1.800 13.800 9.900 ;
        RECT 12.600 8.700 15.900 9.900 ;
        RECT 14.700 10.800 18.600 12.000 ;
        RECT 14.700 8.700 15.900 15.300 ;
        RECT 12.600 14.100 15.900 15.300 ;
        RECT 12.600 14.100 13.800 28.200 ;
        RECT 19.800 16.200 21.000 28.200 ;
        RECT 17.400 14.100 18.900 15.300 ;
        RECT 17.400 15.000 21.000 15.300 ;
        RECT 17.400 14.100 18.600 28.200 ;
        RECT 17.400 1.800 18.600 9.900 ;
        RECT 17.400 8.700 21.000 9.900 ;
        RECT 19.800 8.700 21.000 12.000 ;
        RECT 19.800 1.800 21.000 7.800 ;
  END 
END CLKBUF1

MACRO CLKBUF2
  CLASS  CORE ;
  FOREIGN CLKBUF2 0.000 0.000 ;
  ORIGIN 0.000 0.000 ;
  SIZE 31.200 BY 30.000 ;
  SYMMETRY X Y  ;
  SITE core ;
  PIN A
    DIRECTION INPUT ;
    PORT
      LAYER metal1 ;
        RECT 0.600 9.900 1.800 11.100 ;
    END
  END A
  PIN gnd
    DIRECTION INOUT ;
    USE GROUND ;
    SHAPE ABUTMENT ;
    PORT
      LAYER metal1 ;
        RECT -0.600 -0.900 31.800 0.900 ;
    END
  END gnd
  PIN Y
    DIRECTION OUTPUT ;
    PORT
      LAYER metal1 ;
        RECT 29.400 12.900 30.600 14.100 ;
    END
  END Y
  PIN vdd
    DIRECTION INOUT ;
    USE POWER ;
    SHAPE ABUTMENT ;
    PORT
      LAYER metal1 ;
        RECT -0.600 29.100 31.800 30.900 ;
    END
  END vdd
  OBS 
      LAYER metal1 ;
        RECT 0.600 16.200 1.800 28.200 ;
        RECT 0.600 1.800 1.800 7.800 ;
        RECT 2.700 10.800 3.300 12.000 ;
        RECT 5.400 16.200 6.600 28.200 ;
        RECT 5.400 1.800 6.600 7.800 ;
        RECT 3.000 1.800 4.200 9.900 ;
        RECT 3.000 8.700 5.700 9.900 ;
        RECT 4.500 10.800 8.400 12.000 ;
        RECT 4.500 8.700 5.700 15.300 ;
        RECT 3.000 14.100 5.700 15.300 ;
        RECT 3.000 14.100 4.200 28.200 ;
        RECT 10.200 16.200 11.400 28.200 ;
        RECT 10.200 1.800 11.400 7.800 ;
        RECT 7.800 1.800 9.000 9.900 ;
        RECT 7.800 8.700 11.100 9.900 ;
        RECT 9.900 10.800 13.500 12.000 ;
        RECT 9.900 8.700 11.100 15.300 ;
        RECT 7.800 14.100 11.100 15.300 ;
        RECT 7.800 14.100 9.000 28.200 ;
        RECT 15.000 16.200 16.200 28.200 ;
        RECT 15.000 1.800 16.200 7.800 ;
        RECT 12.600 1.800 13.800 9.900 ;
        RECT 12.600 8.700 15.900 9.900 ;
        RECT 14.700 10.800 18.600 12.000 ;
        RECT 14.700 8.700 15.900 15.300 ;
        RECT 12.600 14.100 15.900 15.300 ;
        RECT 12.600 14.100 13.800 28.200 ;
        RECT 19.800 16.200 21.000 28.200 ;
        RECT 19.800 1.800 21.000 7.800 ;
        RECT 17.400 1.800 18.600 9.900 ;
        RECT 17.400 8.700 21.000 9.900 ;
        RECT 19.800 10.800 22.500 12.000 ;
        RECT 19.800 8.700 21.000 15.300 ;
        RECT 17.400 14.100 21.000 15.300 ;
        RECT 17.400 14.100 18.600 28.200 ;
        RECT 24.600 16.200 25.800 28.200 ;
        RECT 24.600 1.800 25.800 7.800 ;
        RECT 22.200 1.800 23.400 9.900 ;
        RECT 22.200 8.700 24.900 9.900 ;
        RECT 23.700 10.800 27.600 12.000 ;
        RECT 23.700 8.700 24.900 15.300 ;
        RECT 22.200 14.100 24.900 15.300 ;
        RECT 22.200 14.100 23.400 28.200 ;
        RECT 29.400 16.200 30.600 28.200 ;
        RECT 27.000 14.100 28.500 15.300 ;
        RECT 27.000 15.000 30.600 15.300 ;
        RECT 27.000 14.100 28.200 28.200 ;
        RECT 27.000 1.800 28.200 9.900 ;
        RECT 27.000 8.700 30.600 9.900 ;
        RECT 29.400 8.700 30.600 12.000 ;
        RECT 29.400 1.800 30.600 7.800 ;
  END 
END CLKBUF2

MACRO CLKBUF3
  CLASS  CORE ;
  FOREIGN CLKBUF3 0.000 0.000 ;
  ORIGIN 0.000 0.000 ;
  SIZE 40.800 BY 30.000 ;
  SYMMETRY X Y  ;
  SITE core ;
  PIN A
    DIRECTION INPUT ;
    PORT
      LAYER metal1 ;
        RECT 0.600 9.900 1.800 11.100 ;
    END
  END A
  PIN gnd
    DIRECTION INOUT ;
    USE GROUND ;
    SHAPE ABUTMENT ;
    PORT
      LAYER metal1 ;
        RECT -0.600 -0.900 41.400 0.900 ;
    END
  END gnd
  PIN Y
    DIRECTION OUTPUT ;
    PORT
      LAYER metal1 ;
        RECT 39.000 12.900 40.200 14.100 ;
    END
  END Y
  PIN vdd
    DIRECTION INOUT ;
    USE POWER ;
    SHAPE ABUTMENT ;
    PORT
      LAYER metal1 ;
        RECT -0.600 29.100 41.400 30.900 ;
    END
  END vdd
  OBS 
      LAYER metal1 ;
        RECT 0.600 16.200 1.800 28.200 ;
        RECT 0.600 1.800 1.800 7.800 ;
        RECT 2.700 10.800 3.300 12.000 ;
        RECT 5.400 16.200 6.600 28.200 ;
        RECT 5.400 1.800 6.600 7.800 ;
        RECT 3.000 1.800 4.200 9.900 ;
        RECT 3.000 8.700 5.700 9.900 ;
        RECT 4.500 10.800 8.400 12.000 ;
        RECT 4.500 8.700 5.700 15.300 ;
        RECT 3.000 14.100 5.700 15.300 ;
        RECT 3.000 14.100 4.200 28.200 ;
        RECT 10.200 16.200 11.400 28.200 ;
        RECT 10.200 1.800 11.400 7.800 ;
        RECT 7.800 1.800 9.000 9.900 ;
        RECT 7.800 8.700 11.100 9.900 ;
        RECT 9.900 10.800 13.500 12.000 ;
        RECT 9.900 8.700 11.100 15.300 ;
        RECT 7.800 14.100 11.100 15.300 ;
        RECT 7.800 14.100 9.000 28.200 ;
        RECT 15.000 16.200 16.200 28.200 ;
        RECT 15.000 1.800 16.200 7.800 ;
        RECT 12.600 1.800 13.800 9.900 ;
        RECT 12.600 8.700 15.900 9.900 ;
        RECT 14.700 10.800 18.600 12.000 ;
        RECT 14.700 8.700 15.900 15.300 ;
        RECT 12.600 14.100 15.900 15.300 ;
        RECT 12.600 14.100 13.800 28.200 ;
        RECT 19.800 16.200 21.000 28.200 ;
        RECT 19.800 1.800 21.000 7.800 ;
        RECT 17.400 1.800 18.600 9.900 ;
        RECT 17.400 8.700 21.000 9.900 ;
        RECT 19.800 10.800 22.500 12.000 ;
        RECT 19.800 8.700 21.000 15.300 ;
        RECT 17.400 14.100 21.000 15.300 ;
        RECT 17.400 14.100 18.600 28.200 ;
        RECT 24.600 16.200 25.800 28.200 ;
        RECT 24.600 1.800 25.800 7.800 ;
        RECT 22.200 1.800 23.400 9.900 ;
        RECT 22.200 8.700 24.900 9.900 ;
        RECT 23.700 10.800 27.600 12.000 ;
        RECT 23.700 8.700 24.900 15.300 ;
        RECT 22.200 14.100 24.900 15.300 ;
        RECT 22.200 14.100 23.400 28.200 ;
        RECT 29.400 16.200 30.600 28.200 ;
        RECT 29.400 1.800 30.600 7.800 ;
        RECT 27.000 1.800 28.200 9.900 ;
        RECT 27.000 8.700 30.300 9.900 ;
        RECT 29.100 10.800 32.700 12.000 ;
        RECT 29.100 8.700 30.300 15.300 ;
        RECT 27.000 14.100 30.300 15.300 ;
        RECT 27.000 14.100 28.200 28.200 ;
        RECT 34.200 16.200 35.400 28.200 ;
        RECT 34.200 1.800 35.400 7.800 ;
        RECT 31.800 1.800 33.000 9.900 ;
        RECT 31.800 8.700 35.100 9.900 ;
        RECT 33.900 10.800 37.800 12.000 ;
        RECT 33.900 8.700 35.100 15.300 ;
        RECT 31.800 14.100 35.100 15.300 ;
        RECT 31.800 14.100 33.000 28.200 ;
        RECT 39.000 16.200 40.200 28.200 ;
        RECT 36.600 14.100 38.100 15.300 ;
        RECT 36.600 15.000 40.200 15.300 ;
        RECT 36.600 14.100 37.800 28.200 ;
        RECT 36.600 1.800 37.800 9.900 ;
        RECT 36.600 8.700 40.200 9.900 ;
        RECT 39.000 8.700 40.200 12.000 ;
        RECT 39.000 1.800 40.200 7.800 ;
  END 
END CLKBUF3

MACRO PADFC
  CLASS  ENDCAP TOPLEFT ;
  FOREIGN PADFC 0.000 0.000 ;
  ORIGIN 0.000 0.000 ;
  SIZE 300.000 BY 300.000 ;
  SYMMETRY X Y R90  ;
  SITE corner ;
  OBS 
      LAYER metal3 ;
        RECT 0.900 0.900 299.100 299.100 ;
      LAYER metal2 ;
        RECT 99.000 0.000 168.000 299.100 ;
        RECT 172.800 0.000 196.500 299.100 ;
        RECT 202.200 0.000 225.900 299.100 ;
        RECT 230.700 0.000 300.000 69.000 ;
        RECT 0.900 73.800 300.000 98.100 ;
        RECT 0.900 103.200 300.000 126.900 ;
        RECT 0.900 132.300 300.000 201.000 ;
        RECT 0.900 0.900 299.100 299.100 ;
      LAYER metal1 ;
        RECT 99.000 0.000 196.500 299.100 ;
        RECT 202.200 0.000 300.000 98.100 ;
        RECT 0.900 103.200 300.000 201.000 ;
        RECT 0.900 0.900 299.100 299.100 ;
  END 
END PADFC

MACRO PADGND
  CLASS  PAD ;
  FOREIGN PADGND 0.000 0.000 ;
  ORIGIN 0.000 0.000 ;
  SIZE 90.000 BY 300.000 ;
  SYMMETRY R90  ;
  SITE IO ;
  PIN YPAD
    DIRECTION OUTPUT ;
    PORT
      LAYER metal3 ;
        RECT 43.200 260.400 50.100 267.300 ;
    END
  END YPAD
  PIN gnd
    DIRECTION INOUT ;
    USE GROUND ;
    PORT
      CLASS CORE ;
      LAYER metal1 ;
        RECT 30.600 0.000 59.400 1.200 ;
    END
  END gnd
  OBS 
      LAYER metal3 ;
        RECT 0.900 0.900 89.100 258.600 ;
        RECT 0.900 0.900 41.400 299.100 ;
        RECT 51.900 0.900 89.100 299.100 ;
        RECT 0.900 269.100 89.100 299.100 ;
      LAYER metal2 ;
        RECT 0.000 0.000 90.000 69.000 ;
        RECT 0.000 73.800 90.000 97.800 ;
        RECT 0.000 103.200 90.000 127.200 ;
        RECT 0.000 132.000 90.000 201.000 ;
        RECT 0.900 0.000 89.100 299.100 ;
        RECT 6.000 0.000 84.000 300.000 ;
      LAYER metal1 ;
        RECT 0.000 0.300 29.700 97.800 ;
        RECT 60.300 0.300 90.000 97.800 ;
        RECT 0.000 103.200 90.000 201.000 ;
        RECT 0.900 2.700 89.100 299.100 ;
        RECT 6.000 2.700 84.000 300.000 ;
  END 
END PADGND

MACRO PADINC
  CLASS  PAD ;
  FOREIGN PADINC 0.000 0.000 ;
  ORIGIN 0.000 0.000 ;
  SIZE 90.000 BY 300.000 ;
  SYMMETRY R90  ;
  SITE IO ;
  PIN YPAD
    DIRECTION OUTPUT ;
    PORT
      LAYER metal3 ;
        RECT 42.900 263.400 44.700 265.200 ;
    END
  END YPAD
  PIN DI
    DIRECTION OUTPUT ;
    PORT
      LAYER metal2 ;
        RECT 77.700 -0.600 78.900 0.600 ;
        RECT 77.100 0.000 79.800 0.600 ;
    END
  END DI
  OBS 
      LAYER metal3 ;
        RECT 0.900 0.900 75.300 261.600 ;
        RECT 0.900 0.900 41.100 299.100 ;
        RECT 46.500 2.400 89.100 299.100 ;
        RECT 81.600 0.900 89.100 299.100 ;
        RECT 0.900 267.000 89.100 299.100 ;
      LAYER metal2 ;
        RECT 0.000 0.000 36.900 69.000 ;
        RECT 38.400 0.000 51.600 300.000 ;
        RECT 52.800 0.000 72.000 300.000 ;
        RECT 73.200 0.000 75.900 300.000 ;
        RECT 0.000 0.900 75.900 69.000 ;
        RECT 81.000 0.000 90.000 69.000 ;
        RECT 0.000 73.800 90.000 97.800 ;
        RECT 0.000 102.900 90.000 126.600 ;
        RECT 0.000 131.700 90.000 201.000 ;
        RECT 0.900 2.100 89.100 299.100 ;
        RECT 6.000 2.100 84.000 300.000 ;
      LAYER metal1 ;
        RECT 0.000 0.000 90.000 99.600 ;
        RECT 0.000 102.300 90.000 200.700 ;
        RECT 0.900 0.000 89.100 299.100 ;
        RECT 6.000 0.000 84.000 300.000 ;
  END 
END PADINC

MACRO PADOUT
  CLASS  PAD ;
  FOREIGN PADOUT 0.000 0.000 ;
  ORIGIN 0.000 0.000 ;
  SIZE 90.000 BY 300.000 ;
  SYMMETRY R90  ;
  SITE IO ;
  PIN YPAD
    DIRECTION OUTPUT ;
    PORT
      LAYER metal3 ;
        RECT 41.700 259.500 43.500 261.300 ;
    END
  END YPAD
  PIN DO
    DIRECTION INPUT ;
    PORT
      LAYER metal2 ;
        RECT 13.800 -0.600 15.000 0.600 ;
        RECT 13.200 0.000 15.900 0.600 ;
    END
  END DO
  OBS 
      LAYER metal3 ;
        RECT 0.900 0.900 11.400 299.100 ;
        RECT 17.700 0.900 89.100 257.700 ;
        RECT 0.900 2.400 39.900 299.100 ;
        RECT 45.300 0.900 89.100 299.100 ;
        RECT 0.900 263.100 89.100 299.100 ;
      LAYER metal2 ;
        RECT 0.000 0.000 2.100 69.000 ;
        RECT 17.100 0.000 36.900 300.000 ;
        RECT 38.400 0.000 51.600 300.000 ;
        RECT 52.800 0.000 72.000 300.000 ;
        RECT 73.200 0.000 75.900 300.000 ;
        RECT 77.100 0.000 79.800 300.000 ;
        RECT 7.200 0.000 12.000 300.000 ;
        RECT 0.000 0.900 12.000 69.000 ;
        RECT 17.100 0.900 90.000 69.000 ;
        RECT 81.000 0.000 90.000 69.000 ;
        RECT 0.000 73.800 90.000 97.800 ;
        RECT 0.000 102.900 90.000 126.600 ;
        RECT 0.000 131.700 90.000 201.000 ;
        RECT 0.900 2.100 89.100 299.100 ;
        RECT 6.000 2.100 84.000 300.000 ;
      LAYER metal1 ;
        RECT 0.000 0.000 90.000 99.600 ;
        RECT 0.000 102.300 90.000 200.700 ;
        RECT 0.900 0.000 89.100 299.100 ;
        RECT 6.000 0.000 84.000 300.000 ;
  END 
END PADOUT

MACRO PADNC
  CLASS  PAD ;
  FOREIGN PADNC 0.000 0.000 ;
  ORIGIN 0.000 0.000 ;
  SIZE 90.000 BY 300.000 ;
  SYMMETRY R90  ;
  SITE IO ;
  OBS 
      LAYER metal3 ;
        RECT 0.900 0.900 89.100 299.100 ;
      LAYER metal2 ;
        RECT 0.000 0.000 90.000 69.000 ;
        RECT 0.000 73.800 90.000 97.800 ;
        RECT 0.000 103.200 90.000 127.200 ;
        RECT 0.000 132.000 90.000 201.000 ;
        RECT 0.900 0.000 89.100 299.100 ;
        RECT 6.000 0.000 84.000 300.000 ;
      LAYER metal1 ;
        RECT 0.000 0.300 90.000 97.800 ;
        RECT 0.000 103.200 90.000 201.000 ;
        RECT 0.900 0.300 89.100 299.100 ;
        RECT 6.000 0.300 84.000 300.000 ;
  END 
END PADNC

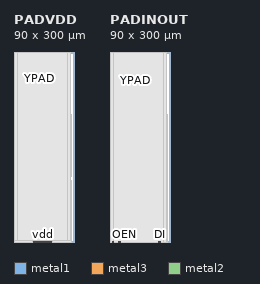
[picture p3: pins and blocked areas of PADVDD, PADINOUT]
MACRO PADVDD
  CLASS  PAD ;
  FOREIGN PADVDD 0.000 0.000 ;
  ORIGIN 0.000 0.000 ;
  SIZE 90.000 BY 300.000 ;
  SYMMETRY R90  ;
  SITE IO ;
  PIN YPAD
    DIRECTION OUTPUT ;
    PORT
      LAYER metal3 ;
        RECT 39.000 256.500 42.900 260.400 ;
    END
  END YPAD
  PIN vdd
    DIRECTION INOUT ;
    USE POWER ;
    PORT
      CLASS CORE ;
      LAYER metal1 ;
        RECT 30.600 0.000 59.400 1.200 ;
    END
  END vdd
  OBS 
      LAYER metal3 ;
        RECT 0.900 0.900 89.100 254.700 ;
        RECT 6.900 0.900 37.200 299.100 ;
        RECT 44.700 0.900 89.100 299.100 ;
        RECT 0.900 262.200 89.100 299.100 ;
      LAYER metal2 ;
        RECT 0.000 0.000 29.400 69.000 ;
        RECT 60.600 0.000 90.000 69.000 ;
        RECT 0.000 73.800 90.000 97.800 ;
        RECT 0.000 103.200 90.000 127.200 ;
        RECT 0.000 132.000 90.000 201.000 ;
        RECT 0.900 2.100 89.100 299.100 ;
        RECT 6.000 2.100 84.000 300.000 ;
      LAYER metal1 ;
        RECT 0.000 0.000 29.700 97.800 ;
        RECT 60.300 0.000 90.000 97.800 ;
        RECT 0.000 103.200 90.000 201.000 ;
        RECT 0.900 2.700 89.100 299.100 ;
        RECT 6.000 2.700 84.000 300.000 ;
  END 
END PADVDD

MACRO PADINOUT
  CLASS  PAD ;
  FOREIGN PADINOUT 0.000 0.000 ;
  ORIGIN 0.000 0.000 ;
  SIZE 90.000 BY 300.000 ;
  SYMMETRY R90  ;
  SITE IO ;
  PIN YPAD
    DIRECTION OUTPUT ;
    PORT
      LAYER metal3 ;
        RECT 38.100 252.600 43.500 257.700 ;
    END
  END YPAD
  PIN DO
    DIRECTION INPUT ;
    PORT
      LAYER metal2 ;
        RECT 13.800 -0.600 15.000 0.600 ;
        RECT 13.200 0.000 15.900 0.600 ;
    END
  END DO
  PIN DI
    DIRECTION OUTPUT ;
    PORT
      LAYER metal2 ;
        RECT 77.700 -0.600 78.900 0.600 ;
        RECT 77.100 0.000 79.800 0.600 ;
    END
  END DI
  PIN OEN
    DIRECTION INPUT ;
    PORT
      LAYER metal2 ;
        RECT 3.900 -0.600 5.100 0.600 ;
        RECT 3.300 0.000 6.000 0.600 ;
    END
  END OEN
  OBS 
      LAYER metal3 ;
        RECT 0.900 0.900 1.500 250.800 ;
        RECT 7.800 0.900 11.400 299.100 ;
        RECT 17.700 0.900 75.300 250.800 ;
        RECT 0.900 2.400 89.100 250.800 ;
        RECT 6.900 2.400 36.300 299.100 ;
        RECT 45.300 2.400 89.100 299.100 ;
        RECT 81.600 0.900 89.100 299.100 ;
        RECT 0.900 259.500 89.100 299.100 ;
      LAYER metal2 ;
        RECT 17.100 0.000 36.900 300.000 ;
        RECT 38.400 0.000 51.600 300.000 ;
        RECT 52.800 0.000 72.000 300.000 ;
        RECT 0.000 0.000 2.100 69.000 ;
        RECT 7.200 0.000 12.000 300.000 ;
        RECT 73.200 0.000 75.900 300.000 ;
        RECT 17.100 0.900 75.900 300.000 ;
        RECT 81.000 0.000 90.000 69.000 ;
        RECT 0.000 73.800 90.000 97.800 ;
        RECT 0.000 102.900 90.000 126.600 ;
        RECT 0.000 131.700 90.000 201.000 ;
        RECT 0.900 2.100 89.100 299.100 ;
        RECT 6.000 2.100 84.000 300.000 ;
      LAYER metal1 ;
        RECT 0.000 0.000 90.000 99.600 ;
        RECT 0.000 102.300 90.000 200.700 ;
        RECT 0.900 0.000 89.100 299.100 ;
        RECT 6.000 0.000 84.000 300.000 ;
  END 
END PADINOUT

END LIBRARY
